VERSION 5.8 ;
BUSBITCHARS "[]" ;
DIVIDERCHAR "/" ;
UNITS
    DATABASE MICRONS 1000 ;
END UNITS

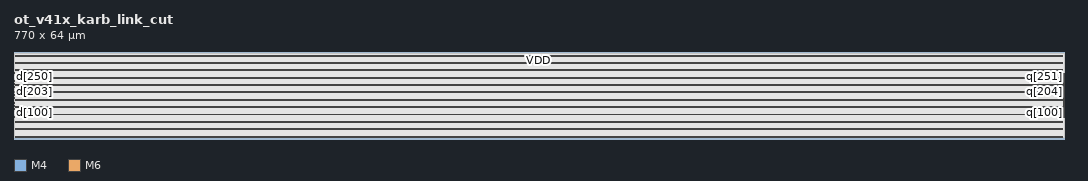
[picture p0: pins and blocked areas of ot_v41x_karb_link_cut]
MACRO ot_v41x_karb_link_cut
  FOREIGN ot_v41x_karb_link_cut 0 0 ;
  CLASS BLOCK ;
  SIZE 770 BY 64 ;
  PIN clk
    DIRECTION INPUT ;
    USE SIGNAL ;
    PORT
      LAYER M4 ;
        RECT  0 15.552 0.084 15.576 ;
    END
  END clk
  PIN d[0]
    DIRECTION INPUT ;
    USE SIGNAL ;
    PORT
      LAYER M4 ;
        RECT  0 15.648 0.084 15.672 ;
    END
  END d[0]
  PIN d[100]
    DIRECTION INPUT ;
    USE SIGNAL ;
    PORT
      LAYER M4 ;
        RECT  0 25.248 0.084 25.272 ;
    END
  END d[100]
  PIN d[101]
    DIRECTION INPUT ;
    USE SIGNAL ;
    PORT
      LAYER M4 ;
        RECT  0 25.344 0.084 25.368 ;
    END
  END d[101]
  PIN d[102]
    DIRECTION INPUT ;
    USE SIGNAL ;
    PORT
      LAYER M4 ;
        RECT  0 25.44 0.084 25.464 ;
    END
  END d[102]
  PIN d[103]
    DIRECTION INPUT ;
    USE SIGNAL ;
    PORT
      LAYER M4 ;
        RECT  0 25.536 0.084 25.56 ;
    END
  END d[103]
  PIN d[104]
    DIRECTION INPUT ;
    USE SIGNAL ;
    PORT
      LAYER M4 ;
        RECT  0 25.632 0.084 25.656 ;
    END
  END d[104]
  PIN d[105]
    DIRECTION INPUT ;
    USE SIGNAL ;
    PORT
      LAYER M4 ;
        RECT  0 25.728 0.084 25.752 ;
    END
  END d[105]
  PIN d[106]
    DIRECTION INPUT ;
    USE SIGNAL ;
    PORT
      LAYER M4 ;
        RECT  0 25.824 0.084 25.848 ;
    END
  END d[106]
  PIN d[107]
    DIRECTION INPUT ;
    USE SIGNAL ;
    PORT
      LAYER M4 ;
        RECT  0 25.92 0.084 25.944 ;
    END
  END d[107]
  PIN d[108]
    DIRECTION INPUT ;
    USE SIGNAL ;
    PORT
      LAYER M4 ;
        RECT  0 26.016 0.084 26.04 ;
    END
  END d[108]
  PIN d[109]
    DIRECTION INPUT ;
    USE SIGNAL ;
    PORT
      LAYER M4 ;
        RECT  0 26.112 0.084 26.136 ;
    END
  END d[109]
  PIN d[10]
    DIRECTION INPUT ;
    USE SIGNAL ;
    PORT
      LAYER M4 ;
        RECT  0 16.608 0.084 16.632 ;
    END
  END d[10]
  PIN d[110]
    DIRECTION INPUT ;
    USE SIGNAL ;
    PORT
      LAYER M4 ;
        RECT  0 26.208 0.084 26.232 ;
    END
  END d[110]
  PIN d[111]
    DIRECTION INPUT ;
    USE SIGNAL ;
    PORT
      LAYER M4 ;
        RECT  0 26.304 0.084 26.328 ;
    END
  END d[111]
  PIN d[112]
    DIRECTION INPUT ;
    USE SIGNAL ;
    PORT
      LAYER M4 ;
        RECT  0 26.4 0.084 26.424 ;
    END
  END d[112]
  PIN d[113]
    DIRECTION INPUT ;
    USE SIGNAL ;
    PORT
      LAYER M4 ;
        RECT  0 26.496 0.084 26.52 ;
    END
  END d[113]
  PIN d[114]
    DIRECTION INPUT ;
    USE SIGNAL ;
    PORT
      LAYER M4 ;
        RECT  0 26.592 0.084 26.616 ;
    END
  END d[114]
  PIN d[115]
    DIRECTION INPUT ;
    USE SIGNAL ;
    PORT
      LAYER M4 ;
        RECT  0 26.688 0.084 26.712 ;
    END
  END d[115]
  PIN d[116]
    DIRECTION INPUT ;
    USE SIGNAL ;
    PORT
      LAYER M4 ;
        RECT  0 26.784 0.084 26.808 ;
    END
  END d[116]
  PIN d[117]
    DIRECTION INPUT ;
    USE SIGNAL ;
    PORT
      LAYER M4 ;
        RECT  0 26.88 0.084 26.904 ;
    END
  END d[117]
  PIN d[118]
    DIRECTION INPUT ;
    USE SIGNAL ;
    PORT
      LAYER M4 ;
        RECT  0 26.976 0.084 27 ;
    END
  END d[118]
  PIN d[119]
    DIRECTION INPUT ;
    USE SIGNAL ;
    PORT
      LAYER M4 ;
        RECT  0 27.072 0.084 27.096 ;
    END
  END d[119]
  PIN d[11]
    DIRECTION INPUT ;
    USE SIGNAL ;
    PORT
      LAYER M4 ;
        RECT  0 16.704 0.084 16.728 ;
    END
  END d[11]
  PIN d[120]
    DIRECTION INPUT ;
    USE SIGNAL ;
    PORT
      LAYER M4 ;
        RECT  0 27.168 0.084 27.192 ;
    END
  END d[120]
  PIN d[121]
    DIRECTION INPUT ;
    USE SIGNAL ;
    PORT
      LAYER M4 ;
        RECT  0 27.264 0.084 27.288 ;
    END
  END d[121]
  PIN d[122]
    DIRECTION INPUT ;
    USE SIGNAL ;
    PORT
      LAYER M4 ;
        RECT  0 27.36 0.084 27.384 ;
    END
  END d[122]
  PIN d[123]
    DIRECTION INPUT ;
    USE SIGNAL ;
    PORT
      LAYER M4 ;
        RECT  0 27.456 0.084 27.48 ;
    END
  END d[123]
  PIN d[124]
    DIRECTION INPUT ;
    USE SIGNAL ;
    PORT
      LAYER M4 ;
        RECT  0 27.552 0.084 27.576 ;
    END
  END d[124]
  PIN d[125]
    DIRECTION INPUT ;
    USE SIGNAL ;
    PORT
      LAYER M4 ;
        RECT  0 27.648 0.084 27.672 ;
    END
  END d[125]
  PIN d[126]
    DIRECTION INPUT ;
    USE SIGNAL ;
    PORT
      LAYER M4 ;
        RECT  0 27.744 0.084 27.768 ;
    END
  END d[126]
  PIN d[127]
    DIRECTION INPUT ;
    USE SIGNAL ;
    PORT
      LAYER M4 ;
        RECT  0 27.84 0.084 27.864 ;
    END
  END d[127]
  PIN d[128]
    DIRECTION INPUT ;
    USE SIGNAL ;
    PORT
      LAYER M4 ;
        RECT  0 27.936 0.084 27.96 ;
    END
  END d[128]
  PIN d[129]
    DIRECTION INPUT ;
    USE SIGNAL ;
    PORT
      LAYER M4 ;
        RECT  0 28.032 0.084 28.056 ;
    END
  END d[129]
  PIN d[12]
    DIRECTION INPUT ;
    USE SIGNAL ;
    PORT
      LAYER M4 ;
        RECT  0 16.8 0.084 16.824 ;
    END
  END d[12]
  PIN d[130]
    DIRECTION INPUT ;
    USE SIGNAL ;
    PORT
      LAYER M4 ;
        RECT  0 28.128 0.084 28.152 ;
    END
  END d[130]
  PIN d[131]
    DIRECTION INPUT ;
    USE SIGNAL ;
    PORT
      LAYER M4 ;
        RECT  0 28.224 0.084 28.248 ;
    END
  END d[131]
  PIN d[132]
    DIRECTION INPUT ;
    USE SIGNAL ;
    PORT
      LAYER M4 ;
        RECT  0 28.32 0.084 28.344 ;
    END
  END d[132]
  PIN d[133]
    DIRECTION INPUT ;
    USE SIGNAL ;
    PORT
      LAYER M4 ;
        RECT  0 28.416 0.084 28.44 ;
    END
  END d[133]
  PIN d[134]
    DIRECTION INPUT ;
    USE SIGNAL ;
    PORT
      LAYER M4 ;
        RECT  0 28.512 0.084 28.536 ;
    END
  END d[134]
  PIN d[135]
    DIRECTION INPUT ;
    USE SIGNAL ;
    PORT
      LAYER M4 ;
        RECT  0 28.608 0.084 28.632 ;
    END
  END d[135]
  PIN d[136]
    DIRECTION INPUT ;
    USE SIGNAL ;
    PORT
      LAYER M4 ;
        RECT  0 28.704 0.084 28.728 ;
    END
  END d[136]
  PIN d[137]
    DIRECTION INPUT ;
    USE SIGNAL ;
    PORT
      LAYER M4 ;
        RECT  0 28.8 0.084 28.824 ;
    END
  END d[137]
  PIN d[138]
    DIRECTION INPUT ;
    USE SIGNAL ;
    PORT
      LAYER M4 ;
        RECT  0 28.896 0.084 28.92 ;
    END
  END d[138]
  PIN d[139]
    DIRECTION INPUT ;
    USE SIGNAL ;
    PORT
      LAYER M4 ;
        RECT  0 28.992 0.084 29.016 ;
    END
  END d[139]
  PIN d[13]
    DIRECTION INPUT ;
    USE SIGNAL ;
    PORT
      LAYER M4 ;
        RECT  0 16.896 0.084 16.92 ;
    END
  END d[13]
  PIN d[140]
    DIRECTION INPUT ;
    USE SIGNAL ;
    PORT
      LAYER M4 ;
        RECT  0 29.088 0.084 29.112 ;
    END
  END d[140]
  PIN d[141]
    DIRECTION INPUT ;
    USE SIGNAL ;
    PORT
      LAYER M4 ;
        RECT  0 29.184 0.084 29.208 ;
    END
  END d[141]
  PIN d[142]
    DIRECTION INPUT ;
    USE SIGNAL ;
    PORT
      LAYER M4 ;
        RECT  0 29.28 0.084 29.304 ;
    END
  END d[142]
  PIN d[143]
    DIRECTION INPUT ;
    USE SIGNAL ;
    PORT
      LAYER M4 ;
        RECT  0 29.376 0.084 29.4 ;
    END
  END d[143]
  PIN d[144]
    DIRECTION INPUT ;
    USE SIGNAL ;
    PORT
      LAYER M4 ;
        RECT  0 29.472 0.084 29.496 ;
    END
  END d[144]
  PIN d[145]
    DIRECTION INPUT ;
    USE SIGNAL ;
    PORT
      LAYER M4 ;
        RECT  0 29.568 0.084 29.592 ;
    END
  END d[145]
  PIN d[146]
    DIRECTION INPUT ;
    USE SIGNAL ;
    PORT
      LAYER M4 ;
        RECT  0 29.664 0.084 29.688 ;
    END
  END d[146]
  PIN d[147]
    DIRECTION INPUT ;
    USE SIGNAL ;
    PORT
      LAYER M4 ;
        RECT  0 29.76 0.084 29.784 ;
    END
  END d[147]
  PIN d[148]
    DIRECTION INPUT ;
    USE SIGNAL ;
    PORT
      LAYER M4 ;
        RECT  0 29.856 0.084 29.88 ;
    END
  END d[148]
  PIN d[149]
    DIRECTION INPUT ;
    USE SIGNAL ;
    PORT
      LAYER M4 ;
        RECT  0 29.952 0.084 29.976 ;
    END
  END d[149]
  PIN d[14]
    DIRECTION INPUT ;
    USE SIGNAL ;
    PORT
      LAYER M4 ;
        RECT  0 16.992 0.084 17.016 ;
    END
  END d[14]
  PIN d[150]
    DIRECTION INPUT ;
    USE SIGNAL ;
    PORT
      LAYER M4 ;
        RECT  0 30.048 0.084 30.072 ;
    END
  END d[150]
  PIN d[151]
    DIRECTION INPUT ;
    USE SIGNAL ;
    PORT
      LAYER M4 ;
        RECT  0 30.144 0.084 30.168 ;
    END
  END d[151]
  PIN d[152]
    DIRECTION INPUT ;
    USE SIGNAL ;
    PORT
      LAYER M4 ;
        RECT  0 30.24 0.084 30.264 ;
    END
  END d[152]
  PIN d[153]
    DIRECTION INPUT ;
    USE SIGNAL ;
    PORT
      LAYER M4 ;
        RECT  0 30.336 0.084 30.36 ;
    END
  END d[153]
  PIN d[154]
    DIRECTION INPUT ;
    USE SIGNAL ;
    PORT
      LAYER M4 ;
        RECT  0 30.432 0.084 30.456 ;
    END
  END d[154]
  PIN d[155]
    DIRECTION INPUT ;
    USE SIGNAL ;
    PORT
      LAYER M4 ;
        RECT  0 30.528 0.084 30.552 ;
    END
  END d[155]
  PIN d[156]
    DIRECTION INPUT ;
    USE SIGNAL ;
    PORT
      LAYER M4 ;
        RECT  0 30.624 0.084 30.648 ;
    END
  END d[156]
  PIN d[157]
    DIRECTION INPUT ;
    USE SIGNAL ;
    PORT
      LAYER M4 ;
        RECT  0 30.72 0.084 30.744 ;
    END
  END d[157]
  PIN d[158]
    DIRECTION INPUT ;
    USE SIGNAL ;
    PORT
      LAYER M4 ;
        RECT  0 30.816 0.084 30.84 ;
    END
  END d[158]
  PIN d[159]
    DIRECTION INPUT ;
    USE SIGNAL ;
    PORT
      LAYER M4 ;
        RECT  0 30.912 0.084 30.936 ;
    END
  END d[159]
  PIN d[15]
    DIRECTION INPUT ;
    USE SIGNAL ;
    PORT
      LAYER M4 ;
        RECT  0 17.088 0.084 17.112 ;
    END
  END d[15]
  PIN d[160]
    DIRECTION INPUT ;
    USE SIGNAL ;
    PORT
      LAYER M4 ;
        RECT  0 31.008 0.084 31.032 ;
    END
  END d[160]
  PIN d[161]
    DIRECTION INPUT ;
    USE SIGNAL ;
    PORT
      LAYER M4 ;
        RECT  0 31.104 0.084 31.128 ;
    END
  END d[161]
  PIN d[162]
    DIRECTION INPUT ;
    USE SIGNAL ;
    PORT
      LAYER M4 ;
        RECT  0 31.2 0.084 31.224 ;
    END
  END d[162]
  PIN d[163]
    DIRECTION INPUT ;
    USE SIGNAL ;
    PORT
      LAYER M4 ;
        RECT  0 31.296 0.084 31.32 ;
    END
  END d[163]
  PIN d[164]
    DIRECTION INPUT ;
    USE SIGNAL ;
    PORT
      LAYER M4 ;
        RECT  0 31.392 0.084 31.416 ;
    END
  END d[164]
  PIN d[165]
    DIRECTION INPUT ;
    USE SIGNAL ;
    PORT
      LAYER M4 ;
        RECT  0 31.488 0.084 31.512 ;
    END
  END d[165]
  PIN d[166]
    DIRECTION INPUT ;
    USE SIGNAL ;
    PORT
      LAYER M4 ;
        RECT  0 31.584 0.084 31.608 ;
    END
  END d[166]
  PIN d[167]
    DIRECTION INPUT ;
    USE SIGNAL ;
    PORT
      LAYER M4 ;
        RECT  0 31.68 0.084 31.704 ;
    END
  END d[167]
  PIN d[168]
    DIRECTION INPUT ;
    USE SIGNAL ;
    PORT
      LAYER M4 ;
        RECT  0 31.776 0.084 31.8 ;
    END
  END d[168]
  PIN d[169]
    DIRECTION INPUT ;
    USE SIGNAL ;
    PORT
      LAYER M4 ;
        RECT  0 31.872 0.084 31.896 ;
    END
  END d[169]
  PIN d[16]
    DIRECTION INPUT ;
    USE SIGNAL ;
    PORT
      LAYER M4 ;
        RECT  0 17.184 0.084 17.208 ;
    END
  END d[16]
  PIN d[170]
    DIRECTION INPUT ;
    USE SIGNAL ;
    PORT
      LAYER M4 ;
        RECT  0 31.968 0.084 31.992 ;
    END
  END d[170]
  PIN d[171]
    DIRECTION INPUT ;
    USE SIGNAL ;
    PORT
      LAYER M4 ;
        RECT  0 32.064 0.084 32.088 ;
    END
  END d[171]
  PIN d[172]
    DIRECTION INPUT ;
    USE SIGNAL ;
    PORT
      LAYER M4 ;
        RECT  0 32.16 0.084 32.184 ;
    END
  END d[172]
  PIN d[173]
    DIRECTION INPUT ;
    USE SIGNAL ;
    PORT
      LAYER M4 ;
        RECT  0 32.256 0.084 32.28 ;
    END
  END d[173]
  PIN d[174]
    DIRECTION INPUT ;
    USE SIGNAL ;
    PORT
      LAYER M4 ;
        RECT  0 32.352 0.084 32.376 ;
    END
  END d[174]
  PIN d[175]
    DIRECTION INPUT ;
    USE SIGNAL ;
    PORT
      LAYER M4 ;
        RECT  0 32.448 0.084 32.472 ;
    END
  END d[175]
  PIN d[176]
    DIRECTION INPUT ;
    USE SIGNAL ;
    PORT
      LAYER M4 ;
        RECT  0 32.544 0.084 32.568 ;
    END
  END d[176]
  PIN d[177]
    DIRECTION INPUT ;
    USE SIGNAL ;
    PORT
      LAYER M4 ;
        RECT  0 32.64 0.084 32.664 ;
    END
  END d[177]
  PIN d[178]
    DIRECTION INPUT ;
    USE SIGNAL ;
    PORT
      LAYER M4 ;
        RECT  0 32.736 0.084 32.76 ;
    END
  END d[178]
  PIN d[179]
    DIRECTION INPUT ;
    USE SIGNAL ;
    PORT
      LAYER M4 ;
        RECT  0 32.832 0.084 32.856 ;
    END
  END d[179]
  PIN d[17]
    DIRECTION INPUT ;
    USE SIGNAL ;
    PORT
      LAYER M4 ;
        RECT  0 17.28 0.084 17.304 ;
    END
  END d[17]
  PIN d[180]
    DIRECTION INPUT ;
    USE SIGNAL ;
    PORT
      LAYER M4 ;
        RECT  0 32.928 0.084 32.952 ;
    END
  END d[180]
  PIN d[181]
    DIRECTION INPUT ;
    USE SIGNAL ;
    PORT
      LAYER M4 ;
        RECT  0 33.024 0.084 33.048 ;
    END
  END d[181]
  PIN d[182]
    DIRECTION INPUT ;
    USE SIGNAL ;
    PORT
      LAYER M4 ;
        RECT  0 33.12 0.084 33.144 ;
    END
  END d[182]
  PIN d[183]
    DIRECTION INPUT ;
    USE SIGNAL ;
    PORT
      LAYER M4 ;
        RECT  0 33.216 0.084 33.24 ;
    END
  END d[183]
  PIN d[184]
    DIRECTION INPUT ;
    USE SIGNAL ;
    PORT
      LAYER M4 ;
        RECT  0 33.312 0.084 33.336 ;
    END
  END d[184]
  PIN d[185]
    DIRECTION INPUT ;
    USE SIGNAL ;
    PORT
      LAYER M4 ;
        RECT  0 33.408 0.084 33.432 ;
    END
  END d[185]
  PIN d[186]
    DIRECTION INPUT ;
    USE SIGNAL ;
    PORT
      LAYER M4 ;
        RECT  0 33.504 0.084 33.528 ;
    END
  END d[186]
  PIN d[187]
    DIRECTION INPUT ;
    USE SIGNAL ;
    PORT
      LAYER M4 ;
        RECT  0 33.6 0.084 33.624 ;
    END
  END d[187]
  PIN d[188]
    DIRECTION INPUT ;
    USE SIGNAL ;
    PORT
      LAYER M4 ;
        RECT  0 33.696 0.084 33.72 ;
    END
  END d[188]
  PIN d[189]
    DIRECTION INPUT ;
    USE SIGNAL ;
    PORT
      LAYER M4 ;
        RECT  0 33.792 0.084 33.816 ;
    END
  END d[189]
  PIN d[18]
    DIRECTION INPUT ;
    USE SIGNAL ;
    PORT
      LAYER M4 ;
        RECT  0 17.376 0.084 17.4 ;
    END
  END d[18]
  PIN d[190]
    DIRECTION INPUT ;
    USE SIGNAL ;
    PORT
      LAYER M4 ;
        RECT  0 33.888 0.084 33.912 ;
    END
  END d[190]
  PIN d[191]
    DIRECTION INPUT ;
    USE SIGNAL ;
    PORT
      LAYER M4 ;
        RECT  0 33.984 0.084 34.008 ;
    END
  END d[191]
  PIN d[192]
    DIRECTION INPUT ;
    USE SIGNAL ;
    PORT
      LAYER M4 ;
        RECT  0 34.08 0.084 34.104 ;
    END
  END d[192]
  PIN d[193]
    DIRECTION INPUT ;
    USE SIGNAL ;
    PORT
      LAYER M4 ;
        RECT  0 34.176 0.084 34.2 ;
    END
  END d[193]
  PIN d[194]
    DIRECTION INPUT ;
    USE SIGNAL ;
    PORT
      LAYER M4 ;
        RECT  0 34.272 0.084 34.296 ;
    END
  END d[194]
  PIN d[195]
    DIRECTION INPUT ;
    USE SIGNAL ;
    PORT
      LAYER M4 ;
        RECT  0 34.368 0.084 34.392 ;
    END
  END d[195]
  PIN d[196]
    DIRECTION INPUT ;
    USE SIGNAL ;
    PORT
      LAYER M4 ;
        RECT  0 34.464 0.084 34.488 ;
    END
  END d[196]
  PIN d[197]
    DIRECTION INPUT ;
    USE SIGNAL ;
    PORT
      LAYER M4 ;
        RECT  0 34.56 0.084 34.584 ;
    END
  END d[197]
  PIN d[198]
    DIRECTION INPUT ;
    USE SIGNAL ;
    PORT
      LAYER M4 ;
        RECT  0 34.656 0.084 34.68 ;
    END
  END d[198]
  PIN d[199]
    DIRECTION INPUT ;
    USE SIGNAL ;
    PORT
      LAYER M4 ;
        RECT  0 34.752 0.084 34.776 ;
    END
  END d[199]
  PIN d[19]
    DIRECTION INPUT ;
    USE SIGNAL ;
    PORT
      LAYER M4 ;
        RECT  0 17.472 0.084 17.496 ;
    END
  END d[19]
  PIN d[1]
    DIRECTION INPUT ;
    USE SIGNAL ;
    PORT
      LAYER M4 ;
        RECT  0 15.744 0.084 15.768 ;
    END
  END d[1]
  PIN d[200]
    DIRECTION INPUT ;
    USE SIGNAL ;
    PORT
      LAYER M4 ;
        RECT  0 34.848 0.084 34.872 ;
    END
  END d[200]
  PIN d[201]
    DIRECTION INPUT ;
    USE SIGNAL ;
    PORT
      LAYER M4 ;
        RECT  0 34.944 0.084 34.968 ;
    END
  END d[201]
  PIN d[202]
    DIRECTION INPUT ;
    USE SIGNAL ;
    PORT
      LAYER M4 ;
        RECT  0 35.04 0.084 35.064 ;
    END
  END d[202]
  PIN d[203]
    DIRECTION INPUT ;
    USE SIGNAL ;
    PORT
      LAYER M4 ;
        RECT  0 35.136 0.084 35.16 ;
    END
  END d[203]
  PIN d[204]
    DIRECTION INPUT ;
    USE SIGNAL ;
    PORT
      LAYER M4 ;
        RECT  0 35.232 0.084 35.256 ;
    END
  END d[204]
  PIN d[205]
    DIRECTION INPUT ;
    USE SIGNAL ;
    PORT
      LAYER M4 ;
        RECT  0 35.328 0.084 35.352 ;
    END
  END d[205]
  PIN d[206]
    DIRECTION INPUT ;
    USE SIGNAL ;
    PORT
      LAYER M4 ;
        RECT  0 35.424 0.084 35.448 ;
    END
  END d[206]
  PIN d[207]
    DIRECTION INPUT ;
    USE SIGNAL ;
    PORT
      LAYER M4 ;
        RECT  0 35.52 0.084 35.544 ;
    END
  END d[207]
  PIN d[208]
    DIRECTION INPUT ;
    USE SIGNAL ;
    PORT
      LAYER M4 ;
        RECT  0 35.616 0.084 35.64 ;
    END
  END d[208]
  PIN d[209]
    DIRECTION INPUT ;
    USE SIGNAL ;
    PORT
      LAYER M4 ;
        RECT  0 35.712 0.084 35.736 ;
    END
  END d[209]
  PIN d[20]
    DIRECTION INPUT ;
    USE SIGNAL ;
    PORT
      LAYER M4 ;
        RECT  0 17.568 0.084 17.592 ;
    END
  END d[20]
  PIN d[210]
    DIRECTION INPUT ;
    USE SIGNAL ;
    PORT
      LAYER M4 ;
        RECT  0 35.808 0.084 35.832 ;
    END
  END d[210]
  PIN d[211]
    DIRECTION INPUT ;
    USE SIGNAL ;
    PORT
      LAYER M4 ;
        RECT  0 35.904 0.084 35.928 ;
    END
  END d[211]
  PIN d[212]
    DIRECTION INPUT ;
    USE SIGNAL ;
    PORT
      LAYER M4 ;
        RECT  0 36 0.084 36.024 ;
    END
  END d[212]
  PIN d[213]
    DIRECTION INPUT ;
    USE SIGNAL ;
    PORT
      LAYER M4 ;
        RECT  0 36.096 0.084 36.12 ;
    END
  END d[213]
  PIN d[214]
    DIRECTION INPUT ;
    USE SIGNAL ;
    PORT
      LAYER M4 ;
        RECT  0 36.192 0.084 36.216 ;
    END
  END d[214]
  PIN d[215]
    DIRECTION INPUT ;
    USE SIGNAL ;
    PORT
      LAYER M4 ;
        RECT  0 36.288 0.084 36.312 ;
    END
  END d[215]
  PIN d[216]
    DIRECTION INPUT ;
    USE SIGNAL ;
    PORT
      LAYER M4 ;
        RECT  0 36.384 0.084 36.408 ;
    END
  END d[216]
  PIN d[217]
    DIRECTION INPUT ;
    USE SIGNAL ;
    PORT
      LAYER M4 ;
        RECT  0 36.48 0.084 36.504 ;
    END
  END d[217]
  PIN d[218]
    DIRECTION INPUT ;
    USE SIGNAL ;
    PORT
      LAYER M4 ;
        RECT  0 36.576 0.084 36.6 ;
    END
  END d[218]
  PIN d[219]
    DIRECTION INPUT ;
    USE SIGNAL ;
    PORT
      LAYER M4 ;
        RECT  0 36.672 0.084 36.696 ;
    END
  END d[219]
  PIN d[21]
    DIRECTION INPUT ;
    USE SIGNAL ;
    PORT
      LAYER M4 ;
        RECT  0 17.664 0.084 17.688 ;
    END
  END d[21]
  PIN d[220]
    DIRECTION INPUT ;
    USE SIGNAL ;
    PORT
      LAYER M4 ;
        RECT  0 36.768 0.084 36.792 ;
    END
  END d[220]
  PIN d[221]
    DIRECTION INPUT ;
    USE SIGNAL ;
    PORT
      LAYER M4 ;
        RECT  0 36.864 0.084 36.888 ;
    END
  END d[221]
  PIN d[222]
    DIRECTION INPUT ;
    USE SIGNAL ;
    PORT
      LAYER M4 ;
        RECT  0 36.96 0.084 36.984 ;
    END
  END d[222]
  PIN d[223]
    DIRECTION INPUT ;
    USE SIGNAL ;
    PORT
      LAYER M4 ;
        RECT  0 37.056 0.084 37.08 ;
    END
  END d[223]
  PIN d[224]
    DIRECTION INPUT ;
    USE SIGNAL ;
    PORT
      LAYER M4 ;
        RECT  0 37.152 0.084 37.176 ;
    END
  END d[224]
  PIN d[225]
    DIRECTION INPUT ;
    USE SIGNAL ;
    PORT
      LAYER M4 ;
        RECT  0 37.248 0.084 37.272 ;
    END
  END d[225]
  PIN d[226]
    DIRECTION INPUT ;
    USE SIGNAL ;
    PORT
      LAYER M4 ;
        RECT  0 37.344 0.084 37.368 ;
    END
  END d[226]
  PIN d[227]
    DIRECTION INPUT ;
    USE SIGNAL ;
    PORT
      LAYER M4 ;
        RECT  0 37.44 0.084 37.464 ;
    END
  END d[227]
  PIN d[228]
    DIRECTION INPUT ;
    USE SIGNAL ;
    PORT
      LAYER M4 ;
        RECT  0 37.536 0.084 37.56 ;
    END
  END d[228]
  PIN d[229]
    DIRECTION INPUT ;
    USE SIGNAL ;
    PORT
      LAYER M4 ;
        RECT  0 37.632 0.084 37.656 ;
    END
  END d[229]
  PIN d[22]
    DIRECTION INPUT ;
    USE SIGNAL ;
    PORT
      LAYER M4 ;
        RECT  0 17.76 0.084 17.784 ;
    END
  END d[22]
  PIN d[230]
    DIRECTION INPUT ;
    USE SIGNAL ;
    PORT
      LAYER M4 ;
        RECT  0 37.728 0.084 37.752 ;
    END
  END d[230]
  PIN d[231]
    DIRECTION INPUT ;
    USE SIGNAL ;
    PORT
      LAYER M4 ;
        RECT  0 37.824 0.084 37.848 ;
    END
  END d[231]
  PIN d[232]
    DIRECTION INPUT ;
    USE SIGNAL ;
    PORT
      LAYER M4 ;
        RECT  0 37.92 0.084 37.944 ;
    END
  END d[232]
  PIN d[233]
    DIRECTION INPUT ;
    USE SIGNAL ;
    PORT
      LAYER M4 ;
        RECT  0 38.016 0.084 38.04 ;
    END
  END d[233]
  PIN d[234]
    DIRECTION INPUT ;
    USE SIGNAL ;
    PORT
      LAYER M4 ;
        RECT  0 38.112 0.084 38.136 ;
    END
  END d[234]
  PIN d[235]
    DIRECTION INPUT ;
    USE SIGNAL ;
    PORT
      LAYER M4 ;
        RECT  0 38.208 0.084 38.232 ;
    END
  END d[235]
  PIN d[236]
    DIRECTION INPUT ;
    USE SIGNAL ;
    PORT
      LAYER M4 ;
        RECT  0 38.304 0.084 38.328 ;
    END
  END d[236]
  PIN d[237]
    DIRECTION INPUT ;
    USE SIGNAL ;
    PORT
      LAYER M4 ;
        RECT  0 38.4 0.084 38.424 ;
    END
  END d[237]
  PIN d[238]
    DIRECTION INPUT ;
    USE SIGNAL ;
    PORT
      LAYER M4 ;
        RECT  0 38.496 0.084 38.52 ;
    END
  END d[238]
  PIN d[239]
    DIRECTION INPUT ;
    USE SIGNAL ;
    PORT
      LAYER M4 ;
        RECT  0 38.592 0.084 38.616 ;
    END
  END d[239]
  PIN d[23]
    DIRECTION INPUT ;
    USE SIGNAL ;
    PORT
      LAYER M4 ;
        RECT  0 17.856 0.084 17.88 ;
    END
  END d[23]
  PIN d[240]
    DIRECTION INPUT ;
    USE SIGNAL ;
    PORT
      LAYER M4 ;
        RECT  0 38.688 0.084 38.712 ;
    END
  END d[240]
  PIN d[241]
    DIRECTION INPUT ;
    USE SIGNAL ;
    PORT
      LAYER M4 ;
        RECT  0 38.784 0.084 38.808 ;
    END
  END d[241]
  PIN d[242]
    DIRECTION INPUT ;
    USE SIGNAL ;
    PORT
      LAYER M4 ;
        RECT  0 38.88 0.084 38.904 ;
    END
  END d[242]
  PIN d[243]
    DIRECTION INPUT ;
    USE SIGNAL ;
    PORT
      LAYER M4 ;
        RECT  0 38.976 0.084 39 ;
    END
  END d[243]
  PIN d[244]
    DIRECTION INPUT ;
    USE SIGNAL ;
    PORT
      LAYER M4 ;
        RECT  0 39.072 0.084 39.096 ;
    END
  END d[244]
  PIN d[245]
    DIRECTION INPUT ;
    USE SIGNAL ;
    PORT
      LAYER M4 ;
        RECT  0 39.168 0.084 39.192 ;
    END
  END d[245]
  PIN d[246]
    DIRECTION INPUT ;
    USE SIGNAL ;
    PORT
      LAYER M4 ;
        RECT  0 39.264 0.084 39.288 ;
    END
  END d[246]
  PIN d[247]
    DIRECTION INPUT ;
    USE SIGNAL ;
    PORT
      LAYER M4 ;
        RECT  0 39.36 0.084 39.384 ;
    END
  END d[247]
  PIN d[248]
    DIRECTION INPUT ;
    USE SIGNAL ;
    PORT
      LAYER M4 ;
        RECT  0 39.456 0.084 39.48 ;
    END
  END d[248]
  PIN d[249]
    DIRECTION INPUT ;
    USE SIGNAL ;
    PORT
      LAYER M4 ;
        RECT  0 39.552 0.084 39.576 ;
    END
  END d[249]
  PIN d[24]
    DIRECTION INPUT ;
    USE SIGNAL ;
    PORT
      LAYER M4 ;
        RECT  0 17.952 0.084 17.976 ;
    END
  END d[24]
  PIN d[250]
    DIRECTION INPUT ;
    USE SIGNAL ;
    PORT
      LAYER M4 ;
        RECT  0 39.648 0.084 39.672 ;
    END
  END d[250]
  PIN d[251]
    DIRECTION INPUT ;
    USE SIGNAL ;
    PORT
      LAYER M4 ;
        RECT  0 39.744 0.084 39.768 ;
    END
  END d[251]
  PIN d[252]
    DIRECTION INPUT ;
    USE SIGNAL ;
    PORT
      LAYER M4 ;
        RECT  0 39.84 0.084 39.864 ;
    END
  END d[252]
  PIN d[253]
    DIRECTION INPUT ;
    USE SIGNAL ;
    PORT
      LAYER M4 ;
        RECT  0 39.936 0.084 39.96 ;
    END
  END d[253]
  PIN d[254]
    DIRECTION INPUT ;
    USE SIGNAL ;
    PORT
      LAYER M4 ;
        RECT  0 40.032 0.084 40.056 ;
    END
  END d[254]
  PIN d[255]
    DIRECTION INPUT ;
    USE SIGNAL ;
    PORT
      LAYER M4 ;
        RECT  0 40.128 0.084 40.152 ;
    END
  END d[255]
  PIN d[256]
    DIRECTION INPUT ;
    USE SIGNAL ;
    PORT
      LAYER M4 ;
        RECT  0 40.224 0.084 40.248 ;
    END
  END d[256]
  PIN d[257]
    DIRECTION INPUT ;
    USE SIGNAL ;
    PORT
      LAYER M4 ;
        RECT  0 40.32 0.084 40.344 ;
    END
  END d[257]
  PIN d[258]
    DIRECTION INPUT ;
    USE SIGNAL ;
    PORT
      LAYER M4 ;
        RECT  0 40.416 0.084 40.44 ;
    END
  END d[258]
  PIN d[259]
    DIRECTION INPUT ;
    USE SIGNAL ;
    PORT
      LAYER M4 ;
        RECT  0 40.512 0.084 40.536 ;
    END
  END d[259]
  PIN d[25]
    DIRECTION INPUT ;
    USE SIGNAL ;
    PORT
      LAYER M4 ;
        RECT  0 18.048 0.084 18.072 ;
    END
  END d[25]
  PIN d[260]
    DIRECTION INPUT ;
    USE SIGNAL ;
    PORT
      LAYER M4 ;
        RECT  0 40.608 0.084 40.632 ;
    END
  END d[260]
  PIN d[261]
    DIRECTION INPUT ;
    USE SIGNAL ;
    PORT
      LAYER M4 ;
        RECT  0 40.704 0.084 40.728 ;
    END
  END d[261]
  PIN d[262]
    DIRECTION INPUT ;
    USE SIGNAL ;
    PORT
      LAYER M4 ;
        RECT  0 40.8 0.084 40.824 ;
    END
  END d[262]
  PIN d[263]
    DIRECTION INPUT ;
    USE SIGNAL ;
    PORT
      LAYER M4 ;
        RECT  0 40.896 0.084 40.92 ;
    END
  END d[263]
  PIN d[264]
    DIRECTION INPUT ;
    USE SIGNAL ;
    PORT
      LAYER M4 ;
        RECT  0 40.992 0.084 41.016 ;
    END
  END d[264]
  PIN d[265]
    DIRECTION INPUT ;
    USE SIGNAL ;
    PORT
      LAYER M4 ;
        RECT  0 41.088 0.084 41.112 ;
    END
  END d[265]
  PIN d[266]
    DIRECTION INPUT ;
    USE SIGNAL ;
    PORT
      LAYER M4 ;
        RECT  0 41.184 0.084 41.208 ;
    END
  END d[266]
  PIN d[267]
    DIRECTION INPUT ;
    USE SIGNAL ;
    PORT
      LAYER M4 ;
        RECT  0 41.28 0.084 41.304 ;
    END
  END d[267]
  PIN d[268]
    DIRECTION INPUT ;
    USE SIGNAL ;
    PORT
      LAYER M4 ;
        RECT  0 41.376 0.084 41.4 ;
    END
  END d[268]
  PIN d[269]
    DIRECTION INPUT ;
    USE SIGNAL ;
    PORT
      LAYER M4 ;
        RECT  0 41.472 0.084 41.496 ;
    END
  END d[269]
  PIN d[26]
    DIRECTION INPUT ;
    USE SIGNAL ;
    PORT
      LAYER M4 ;
        RECT  0 18.144 0.084 18.168 ;
    END
  END d[26]
  PIN d[270]
    DIRECTION INPUT ;
    USE SIGNAL ;
    PORT
      LAYER M4 ;
        RECT  0 41.568 0.084 41.592 ;
    END
  END d[270]
  PIN d[271]
    DIRECTION INPUT ;
    USE SIGNAL ;
    PORT
      LAYER M4 ;
        RECT  0 41.664 0.084 41.688 ;
    END
  END d[271]
  PIN d[272]
    DIRECTION INPUT ;
    USE SIGNAL ;
    PORT
      LAYER M4 ;
        RECT  0 41.76 0.084 41.784 ;
    END
  END d[272]
  PIN d[273]
    DIRECTION INPUT ;
    USE SIGNAL ;
    PORT
      LAYER M4 ;
        RECT  0 41.856 0.084 41.88 ;
    END
  END d[273]
  PIN d[274]
    DIRECTION INPUT ;
    USE SIGNAL ;
    PORT
      LAYER M4 ;
        RECT  0 41.952 0.084 41.976 ;
    END
  END d[274]
  PIN d[275]
    DIRECTION INPUT ;
    USE SIGNAL ;
    PORT
      LAYER M4 ;
        RECT  0 42.048 0.084 42.072 ;
    END
  END d[275]
  PIN d[276]
    DIRECTION INPUT ;
    USE SIGNAL ;
    PORT
      LAYER M4 ;
        RECT  0 42.144 0.084 42.168 ;
    END
  END d[276]
  PIN d[277]
    DIRECTION INPUT ;
    USE SIGNAL ;
    PORT
      LAYER M4 ;
        RECT  0 42.24 0.084 42.264 ;
    END
  END d[277]
  PIN d[278]
    DIRECTION INPUT ;
    USE SIGNAL ;
    PORT
      LAYER M4 ;
        RECT  0 42.336 0.084 42.36 ;
    END
  END d[278]
  PIN d[279]
    DIRECTION INPUT ;
    USE SIGNAL ;
    PORT
      LAYER M4 ;
        RECT  0 42.432 0.084 42.456 ;
    END
  END d[279]
  PIN d[27]
    DIRECTION INPUT ;
    USE SIGNAL ;
    PORT
      LAYER M4 ;
        RECT  0 18.24 0.084 18.264 ;
    END
  END d[27]
  PIN d[280]
    DIRECTION INPUT ;
    USE SIGNAL ;
    PORT
      LAYER M4 ;
        RECT  0 42.528 0.084 42.552 ;
    END
  END d[280]
  PIN d[281]
    DIRECTION INPUT ;
    USE SIGNAL ;
    PORT
      LAYER M4 ;
        RECT  0 42.624 0.084 42.648 ;
    END
  END d[281]
  PIN d[282]
    DIRECTION INPUT ;
    USE SIGNAL ;
    PORT
      LAYER M4 ;
        RECT  0 42.72 0.084 42.744 ;
    END
  END d[282]
  PIN d[283]
    DIRECTION INPUT ;
    USE SIGNAL ;
    PORT
      LAYER M4 ;
        RECT  0 42.816 0.084 42.84 ;
    END
  END d[283]
  PIN d[284]
    DIRECTION INPUT ;
    USE SIGNAL ;
    PORT
      LAYER M4 ;
        RECT  0 42.912 0.084 42.936 ;
    END
  END d[284]
  PIN d[285]
    DIRECTION INPUT ;
    USE SIGNAL ;
    PORT
      LAYER M4 ;
        RECT  0 43.008 0.084 43.032 ;
    END
  END d[285]
  PIN d[286]
    DIRECTION INPUT ;
    USE SIGNAL ;
    PORT
      LAYER M4 ;
        RECT  0 43.104 0.084 43.128 ;
    END
  END d[286]
  PIN d[287]
    DIRECTION INPUT ;
    USE SIGNAL ;
    PORT
      LAYER M4 ;
        RECT  0 43.2 0.084 43.224 ;
    END
  END d[287]
  PIN d[288]
    DIRECTION INPUT ;
    USE SIGNAL ;
    PORT
      LAYER M4 ;
        RECT  0 43.296 0.084 43.32 ;
    END
  END d[288]
  PIN d[289]
    DIRECTION INPUT ;
    USE SIGNAL ;
    PORT
      LAYER M4 ;
        RECT  0 43.392 0.084 43.416 ;
    END
  END d[289]
  PIN d[28]
    DIRECTION INPUT ;
    USE SIGNAL ;
    PORT
      LAYER M4 ;
        RECT  0 18.336 0.084 18.36 ;
    END
  END d[28]
  PIN d[290]
    DIRECTION INPUT ;
    USE SIGNAL ;
    PORT
      LAYER M4 ;
        RECT  0 43.488 0.084 43.512 ;
    END
  END d[290]
  PIN d[291]
    DIRECTION INPUT ;
    USE SIGNAL ;
    PORT
      LAYER M4 ;
        RECT  0 43.584 0.084 43.608 ;
    END
  END d[291]
  PIN d[292]
    DIRECTION INPUT ;
    USE SIGNAL ;
    PORT
      LAYER M4 ;
        RECT  0 43.68 0.084 43.704 ;
    END
  END d[292]
  PIN d[293]
    DIRECTION INPUT ;
    USE SIGNAL ;
    PORT
      LAYER M4 ;
        RECT  0 43.776 0.084 43.8 ;
    END
  END d[293]
  PIN d[294]
    DIRECTION INPUT ;
    USE SIGNAL ;
    PORT
      LAYER M4 ;
        RECT  0 43.872 0.084 43.896 ;
    END
  END d[294]
  PIN d[295]
    DIRECTION INPUT ;
    USE SIGNAL ;
    PORT
      LAYER M4 ;
        RECT  0 43.968 0.084 43.992 ;
    END
  END d[295]
  PIN d[296]
    DIRECTION INPUT ;
    USE SIGNAL ;
    PORT
      LAYER M4 ;
        RECT  0 44.064 0.084 44.088 ;
    END
  END d[296]
  PIN d[297]
    DIRECTION INPUT ;
    USE SIGNAL ;
    PORT
      LAYER M4 ;
        RECT  0 44.16 0.084 44.184 ;
    END
  END d[297]
  PIN d[298]
    DIRECTION INPUT ;
    USE SIGNAL ;
    PORT
      LAYER M4 ;
        RECT  0 44.256 0.084 44.28 ;
    END
  END d[298]
  PIN d[299]
    DIRECTION INPUT ;
    USE SIGNAL ;
    PORT
      LAYER M4 ;
        RECT  0 44.352 0.084 44.376 ;
    END
  END d[299]
  PIN d[29]
    DIRECTION INPUT ;
    USE SIGNAL ;
    PORT
      LAYER M4 ;
        RECT  0 18.432 0.084 18.456 ;
    END
  END d[29]
  PIN d[2]
    DIRECTION INPUT ;
    USE SIGNAL ;
    PORT
      LAYER M4 ;
        RECT  0 15.84 0.084 15.864 ;
    END
  END d[2]
  PIN d[300]
    DIRECTION INPUT ;
    USE SIGNAL ;
    PORT
      LAYER M4 ;
        RECT  0 44.448 0.084 44.472 ;
    END
  END d[300]
  PIN d[301]
    DIRECTION INPUT ;
    USE SIGNAL ;
    PORT
      LAYER M4 ;
        RECT  0 44.544 0.084 44.568 ;
    END
  END d[301]
  PIN d[302]
    DIRECTION INPUT ;
    USE SIGNAL ;
    PORT
      LAYER M4 ;
        RECT  0 44.64 0.084 44.664 ;
    END
  END d[302]
  PIN d[303]
    DIRECTION INPUT ;
    USE SIGNAL ;
    PORT
      LAYER M4 ;
        RECT  0 44.736 0.084 44.76 ;
    END
  END d[303]
  PIN d[304]
    DIRECTION INPUT ;
    USE SIGNAL ;
    PORT
      LAYER M4 ;
        RECT  0 44.832 0.084 44.856 ;
    END
  END d[304]
  PIN d[305]
    DIRECTION INPUT ;
    USE SIGNAL ;
    PORT
      LAYER M4 ;
        RECT  0 44.928 0.084 44.952 ;
    END
  END d[305]
  PIN d[306]
    DIRECTION INPUT ;
    USE SIGNAL ;
    PORT
      LAYER M4 ;
        RECT  0 45.024 0.084 45.048 ;
    END
  END d[306]
  PIN d[307]
    DIRECTION INPUT ;
    USE SIGNAL ;
    PORT
      LAYER M4 ;
        RECT  0 45.12 0.084 45.144 ;
    END
  END d[307]
  PIN d[308]
    DIRECTION INPUT ;
    USE SIGNAL ;
    PORT
      LAYER M4 ;
        RECT  0 45.216 0.084 45.24 ;
    END
  END d[308]
  PIN d[309]
    DIRECTION INPUT ;
    USE SIGNAL ;
    PORT
      LAYER M4 ;
        RECT  0 45.312 0.084 45.336 ;
    END
  END d[309]
  PIN d[30]
    DIRECTION INPUT ;
    USE SIGNAL ;
    PORT
      LAYER M4 ;
        RECT  0 18.528 0.084 18.552 ;
    END
  END d[30]
  PIN d[310]
    DIRECTION INPUT ;
    USE SIGNAL ;
    PORT
      LAYER M4 ;
        RECT  0 45.408 0.084 45.432 ;
    END
  END d[310]
  PIN d[311]
    DIRECTION INPUT ;
    USE SIGNAL ;
    PORT
      LAYER M4 ;
        RECT  0 45.504 0.084 45.528 ;
    END
  END d[311]
  PIN d[312]
    DIRECTION INPUT ;
    USE SIGNAL ;
    PORT
      LAYER M4 ;
        RECT  0 45.6 0.084 45.624 ;
    END
  END d[312]
  PIN d[313]
    DIRECTION INPUT ;
    USE SIGNAL ;
    PORT
      LAYER M4 ;
        RECT  0 45.696 0.084 45.72 ;
    END
  END d[313]
  PIN d[314]
    DIRECTION INPUT ;
    USE SIGNAL ;
    PORT
      LAYER M4 ;
        RECT  0 45.792 0.084 45.816 ;
    END
  END d[314]
  PIN d[315]
    DIRECTION INPUT ;
    USE SIGNAL ;
    PORT
      LAYER M4 ;
        RECT  0 45.888 0.084 45.912 ;
    END
  END d[315]
  PIN d[316]
    DIRECTION INPUT ;
    USE SIGNAL ;
    PORT
      LAYER M4 ;
        RECT  0 45.984 0.084 46.008 ;
    END
  END d[316]
  PIN d[317]
    DIRECTION INPUT ;
    USE SIGNAL ;
    PORT
      LAYER M4 ;
        RECT  0 46.08 0.084 46.104 ;
    END
  END d[317]
  PIN d[318]
    DIRECTION INPUT ;
    USE SIGNAL ;
    PORT
      LAYER M4 ;
        RECT  0 46.176 0.084 46.2 ;
    END
  END d[318]
  PIN d[319]
    DIRECTION INPUT ;
    USE SIGNAL ;
    PORT
      LAYER M4 ;
        RECT  0 46.272 0.084 46.296 ;
    END
  END d[319]
  PIN d[31]
    DIRECTION INPUT ;
    USE SIGNAL ;
    PORT
      LAYER M4 ;
        RECT  0 18.624 0.084 18.648 ;
    END
  END d[31]
  PIN d[320]
    DIRECTION INPUT ;
    USE SIGNAL ;
    PORT
      LAYER M4 ;
        RECT  0 46.368 0.084 46.392 ;
    END
  END d[320]
  PIN d[321]
    DIRECTION INPUT ;
    USE SIGNAL ;
    PORT
      LAYER M4 ;
        RECT  0 46.464 0.084 46.488 ;
    END
  END d[321]
  PIN d[322]
    DIRECTION INPUT ;
    USE SIGNAL ;
    PORT
      LAYER M4 ;
        RECT  0 46.56 0.084 46.584 ;
    END
  END d[322]
  PIN d[323]
    DIRECTION INPUT ;
    USE SIGNAL ;
    PORT
      LAYER M4 ;
        RECT  0 46.656 0.084 46.68 ;
    END
  END d[323]
  PIN d[324]
    DIRECTION INPUT ;
    USE SIGNAL ;
    PORT
      LAYER M4 ;
        RECT  0 46.752 0.084 46.776 ;
    END
  END d[324]
  PIN d[325]
    DIRECTION INPUT ;
    USE SIGNAL ;
    PORT
      LAYER M4 ;
        RECT  0 46.848 0.084 46.872 ;
    END
  END d[325]
  PIN d[326]
    DIRECTION INPUT ;
    USE SIGNAL ;
    PORT
      LAYER M4 ;
        RECT  0 46.944 0.084 46.968 ;
    END
  END d[326]
  PIN d[327]
    DIRECTION INPUT ;
    USE SIGNAL ;
    PORT
      LAYER M4 ;
        RECT  0 47.04 0.084 47.064 ;
    END
  END d[327]
  PIN d[328]
    DIRECTION INPUT ;
    USE SIGNAL ;
    PORT
      LAYER M4 ;
        RECT  0 47.136 0.084 47.16 ;
    END
  END d[328]
  PIN d[329]
    DIRECTION INPUT ;
    USE SIGNAL ;
    PORT
      LAYER M4 ;
        RECT  0 47.232 0.084 47.256 ;
    END
  END d[329]
  PIN d[32]
    DIRECTION INPUT ;
    USE SIGNAL ;
    PORT
      LAYER M4 ;
        RECT  0 18.72 0.084 18.744 ;
    END
  END d[32]
  PIN d[330]
    DIRECTION INPUT ;
    USE SIGNAL ;
    PORT
      LAYER M4 ;
        RECT  0 47.328 0.084 47.352 ;
    END
  END d[330]
  PIN d[331]
    DIRECTION INPUT ;
    USE SIGNAL ;
    PORT
      LAYER M4 ;
        RECT  0 47.424 0.084 47.448 ;
    END
  END d[331]
  PIN d[332]
    DIRECTION INPUT ;
    USE SIGNAL ;
    PORT
      LAYER M4 ;
        RECT  0 47.52 0.084 47.544 ;
    END
  END d[332]
  PIN d[333]
    DIRECTION INPUT ;
    USE SIGNAL ;
    PORT
      LAYER M4 ;
        RECT  0 47.616 0.084 47.64 ;
    END
  END d[333]
  PIN d[334]
    DIRECTION INPUT ;
    USE SIGNAL ;
    PORT
      LAYER M4 ;
        RECT  0 47.712 0.084 47.736 ;
    END
  END d[334]
  PIN d[335]
    DIRECTION INPUT ;
    USE SIGNAL ;
    PORT
      LAYER M4 ;
        RECT  0 47.808 0.084 47.832 ;
    END
  END d[335]
  PIN d[336]
    DIRECTION INPUT ;
    USE SIGNAL ;
    PORT
      LAYER M4 ;
        RECT  0 47.904 0.084 47.928 ;
    END
  END d[336]
  PIN d[337]
    DIRECTION INPUT ;
    USE SIGNAL ;
    PORT
      LAYER M4 ;
        RECT  0 48 0.084 48.024 ;
    END
  END d[337]
  PIN d[338]
    DIRECTION INPUT ;
    USE SIGNAL ;
    PORT
      LAYER M4 ;
        RECT  0 48.096 0.084 48.12 ;
    END
  END d[338]
  PIN d[339]
    DIRECTION INPUT ;
    USE SIGNAL ;
    PORT
      LAYER M4 ;
        RECT  0 48.192 0.084 48.216 ;
    END
  END d[339]
  PIN d[33]
    DIRECTION INPUT ;
    USE SIGNAL ;
    PORT
      LAYER M4 ;
        RECT  0 18.816 0.084 18.84 ;
    END
  END d[33]
  PIN d[340]
    DIRECTION INPUT ;
    USE SIGNAL ;
    PORT
      LAYER M4 ;
        RECT  0 48.288 0.084 48.312 ;
    END
  END d[340]
  PIN d[341]
    DIRECTION INPUT ;
    USE SIGNAL ;
    PORT
      LAYER M4 ;
        RECT  0 48.384 0.084 48.408 ;
    END
  END d[341]
  PIN d[34]
    DIRECTION INPUT ;
    USE SIGNAL ;
    PORT
      LAYER M4 ;
        RECT  0 18.912 0.084 18.936 ;
    END
  END d[34]
  PIN d[35]
    DIRECTION INPUT ;
    USE SIGNAL ;
    PORT
      LAYER M4 ;
        RECT  0 19.008 0.084 19.032 ;
    END
  END d[35]
  PIN d[36]
    DIRECTION INPUT ;
    USE SIGNAL ;
    PORT
      LAYER M4 ;
        RECT  0 19.104 0.084 19.128 ;
    END
  END d[36]
  PIN d[37]
    DIRECTION INPUT ;
    USE SIGNAL ;
    PORT
      LAYER M4 ;
        RECT  0 19.2 0.084 19.224 ;
    END
  END d[37]
  PIN d[38]
    DIRECTION INPUT ;
    USE SIGNAL ;
    PORT
      LAYER M4 ;
        RECT  0 19.296 0.084 19.32 ;
    END
  END d[38]
  PIN d[39]
    DIRECTION INPUT ;
    USE SIGNAL ;
    PORT
      LAYER M4 ;
        RECT  0 19.392 0.084 19.416 ;
    END
  END d[39]
  PIN d[3]
    DIRECTION INPUT ;
    USE SIGNAL ;
    PORT
      LAYER M4 ;
        RECT  0 15.936 0.084 15.96 ;
    END
  END d[3]
  PIN d[40]
    DIRECTION INPUT ;
    USE SIGNAL ;
    PORT
      LAYER M4 ;
        RECT  0 19.488 0.084 19.512 ;
    END
  END d[40]
  PIN d[41]
    DIRECTION INPUT ;
    USE SIGNAL ;
    PORT
      LAYER M4 ;
        RECT  0 19.584 0.084 19.608 ;
    END
  END d[41]
  PIN d[42]
    DIRECTION INPUT ;
    USE SIGNAL ;
    PORT
      LAYER M4 ;
        RECT  0 19.68 0.084 19.704 ;
    END
  END d[42]
  PIN d[43]
    DIRECTION INPUT ;
    USE SIGNAL ;
    PORT
      LAYER M4 ;
        RECT  0 19.776 0.084 19.8 ;
    END
  END d[43]
  PIN d[44]
    DIRECTION INPUT ;
    USE SIGNAL ;
    PORT
      LAYER M4 ;
        RECT  0 19.872 0.084 19.896 ;
    END
  END d[44]
  PIN d[45]
    DIRECTION INPUT ;
    USE SIGNAL ;
    PORT
      LAYER M4 ;
        RECT  0 19.968 0.084 19.992 ;
    END
  END d[45]
  PIN d[46]
    DIRECTION INPUT ;
    USE SIGNAL ;
    PORT
      LAYER M4 ;
        RECT  0 20.064 0.084 20.088 ;
    END
  END d[46]
  PIN d[47]
    DIRECTION INPUT ;
    USE SIGNAL ;
    PORT
      LAYER M4 ;
        RECT  0 20.16 0.084 20.184 ;
    END
  END d[47]
  PIN d[48]
    DIRECTION INPUT ;
    USE SIGNAL ;
    PORT
      LAYER M4 ;
        RECT  0 20.256 0.084 20.28 ;
    END
  END d[48]
  PIN d[49]
    DIRECTION INPUT ;
    USE SIGNAL ;
    PORT
      LAYER M4 ;
        RECT  0 20.352 0.084 20.376 ;
    END
  END d[49]
  PIN d[4]
    DIRECTION INPUT ;
    USE SIGNAL ;
    PORT
      LAYER M4 ;
        RECT  0 16.032 0.084 16.056 ;
    END
  END d[4]
  PIN d[50]
    DIRECTION INPUT ;
    USE SIGNAL ;
    PORT
      LAYER M4 ;
        RECT  0 20.448 0.084 20.472 ;
    END
  END d[50]
  PIN d[51]
    DIRECTION INPUT ;
    USE SIGNAL ;
    PORT
      LAYER M4 ;
        RECT  0 20.544 0.084 20.568 ;
    END
  END d[51]
  PIN d[52]
    DIRECTION INPUT ;
    USE SIGNAL ;
    PORT
      LAYER M4 ;
        RECT  0 20.64 0.084 20.664 ;
    END
  END d[52]
  PIN d[53]
    DIRECTION INPUT ;
    USE SIGNAL ;
    PORT
      LAYER M4 ;
        RECT  0 20.736 0.084 20.76 ;
    END
  END d[53]
  PIN d[54]
    DIRECTION INPUT ;
    USE SIGNAL ;
    PORT
      LAYER M4 ;
        RECT  0 20.832 0.084 20.856 ;
    END
  END d[54]
  PIN d[55]
    DIRECTION INPUT ;
    USE SIGNAL ;
    PORT
      LAYER M4 ;
        RECT  0 20.928 0.084 20.952 ;
    END
  END d[55]
  PIN d[56]
    DIRECTION INPUT ;
    USE SIGNAL ;
    PORT
      LAYER M4 ;
        RECT  0 21.024 0.084 21.048 ;
    END
  END d[56]
  PIN d[57]
    DIRECTION INPUT ;
    USE SIGNAL ;
    PORT
      LAYER M4 ;
        RECT  0 21.12 0.084 21.144 ;
    END
  END d[57]
  PIN d[58]
    DIRECTION INPUT ;
    USE SIGNAL ;
    PORT
      LAYER M4 ;
        RECT  0 21.216 0.084 21.24 ;
    END
  END d[58]
  PIN d[59]
    DIRECTION INPUT ;
    USE SIGNAL ;
    PORT
      LAYER M4 ;
        RECT  0 21.312 0.084 21.336 ;
    END
  END d[59]
  PIN d[5]
    DIRECTION INPUT ;
    USE SIGNAL ;
    PORT
      LAYER M4 ;
        RECT  0 16.128 0.084 16.152 ;
    END
  END d[5]
  PIN d[60]
    DIRECTION INPUT ;
    USE SIGNAL ;
    PORT
      LAYER M4 ;
        RECT  0 21.408 0.084 21.432 ;
    END
  END d[60]
  PIN d[61]
    DIRECTION INPUT ;
    USE SIGNAL ;
    PORT
      LAYER M4 ;
        RECT  0 21.504 0.084 21.528 ;
    END
  END d[61]
  PIN d[62]
    DIRECTION INPUT ;
    USE SIGNAL ;
    PORT
      LAYER M4 ;
        RECT  0 21.6 0.084 21.624 ;
    END
  END d[62]
  PIN d[63]
    DIRECTION INPUT ;
    USE SIGNAL ;
    PORT
      LAYER M4 ;
        RECT  0 21.696 0.084 21.72 ;
    END
  END d[63]
  PIN d[64]
    DIRECTION INPUT ;
    USE SIGNAL ;
    PORT
      LAYER M4 ;
        RECT  0 21.792 0.084 21.816 ;
    END
  END d[64]
  PIN d[65]
    DIRECTION INPUT ;
    USE SIGNAL ;
    PORT
      LAYER M4 ;
        RECT  0 21.888 0.084 21.912 ;
    END
  END d[65]
  PIN d[66]
    DIRECTION INPUT ;
    USE SIGNAL ;
    PORT
      LAYER M4 ;
        RECT  0 21.984 0.084 22.008 ;
    END
  END d[66]
  PIN d[67]
    DIRECTION INPUT ;
    USE SIGNAL ;
    PORT
      LAYER M4 ;
        RECT  0 22.08 0.084 22.104 ;
    END
  END d[67]
  PIN d[68]
    DIRECTION INPUT ;
    USE SIGNAL ;
    PORT
      LAYER M4 ;
        RECT  0 22.176 0.084 22.2 ;
    END
  END d[68]
  PIN d[69]
    DIRECTION INPUT ;
    USE SIGNAL ;
    PORT
      LAYER M4 ;
        RECT  0 22.272 0.084 22.296 ;
    END
  END d[69]
  PIN d[6]
    DIRECTION INPUT ;
    USE SIGNAL ;
    PORT
      LAYER M4 ;
        RECT  0 16.224 0.084 16.248 ;
    END
  END d[6]
  PIN d[70]
    DIRECTION INPUT ;
    USE SIGNAL ;
    PORT
      LAYER M4 ;
        RECT  0 22.368 0.084 22.392 ;
    END
  END d[70]
  PIN d[71]
    DIRECTION INPUT ;
    USE SIGNAL ;
    PORT
      LAYER M4 ;
        RECT  0 22.464 0.084 22.488 ;
    END
  END d[71]
  PIN d[72]
    DIRECTION INPUT ;
    USE SIGNAL ;
    PORT
      LAYER M4 ;
        RECT  0 22.56 0.084 22.584 ;
    END
  END d[72]
  PIN d[73]
    DIRECTION INPUT ;
    USE SIGNAL ;
    PORT
      LAYER M4 ;
        RECT  0 22.656 0.084 22.68 ;
    END
  END d[73]
  PIN d[74]
    DIRECTION INPUT ;
    USE SIGNAL ;
    PORT
      LAYER M4 ;
        RECT  0 22.752 0.084 22.776 ;
    END
  END d[74]
  PIN d[75]
    DIRECTION INPUT ;
    USE SIGNAL ;
    PORT
      LAYER M4 ;
        RECT  0 22.848 0.084 22.872 ;
    END
  END d[75]
  PIN d[76]
    DIRECTION INPUT ;
    USE SIGNAL ;
    PORT
      LAYER M4 ;
        RECT  0 22.944 0.084 22.968 ;
    END
  END d[76]
  PIN d[77]
    DIRECTION INPUT ;
    USE SIGNAL ;
    PORT
      LAYER M4 ;
        RECT  0 23.04 0.084 23.064 ;
    END
  END d[77]
  PIN d[78]
    DIRECTION INPUT ;
    USE SIGNAL ;
    PORT
      LAYER M4 ;
        RECT  0 23.136 0.084 23.16 ;
    END
  END d[78]
  PIN d[79]
    DIRECTION INPUT ;
    USE SIGNAL ;
    PORT
      LAYER M4 ;
        RECT  0 23.232 0.084 23.256 ;
    END
  END d[79]
  PIN d[7]
    DIRECTION INPUT ;
    USE SIGNAL ;
    PORT
      LAYER M4 ;
        RECT  0 16.32 0.084 16.344 ;
    END
  END d[7]
  PIN d[80]
    DIRECTION INPUT ;
    USE SIGNAL ;
    PORT
      LAYER M4 ;
        RECT  0 23.328 0.084 23.352 ;
    END
  END d[80]
  PIN d[81]
    DIRECTION INPUT ;
    USE SIGNAL ;
    PORT
      LAYER M4 ;
        RECT  0 23.424 0.084 23.448 ;
    END
  END d[81]
  PIN d[82]
    DIRECTION INPUT ;
    USE SIGNAL ;
    PORT
      LAYER M4 ;
        RECT  0 23.52 0.084 23.544 ;
    END
  END d[82]
  PIN d[83]
    DIRECTION INPUT ;
    USE SIGNAL ;
    PORT
      LAYER M4 ;
        RECT  0 23.616 0.084 23.64 ;
    END
  END d[83]
  PIN d[84]
    DIRECTION INPUT ;
    USE SIGNAL ;
    PORT
      LAYER M4 ;
        RECT  0 23.712 0.084 23.736 ;
    END
  END d[84]
  PIN d[85]
    DIRECTION INPUT ;
    USE SIGNAL ;
    PORT
      LAYER M4 ;
        RECT  0 23.808 0.084 23.832 ;
    END
  END d[85]
  PIN d[86]
    DIRECTION INPUT ;
    USE SIGNAL ;
    PORT
      LAYER M4 ;
        RECT  0 23.904 0.084 23.928 ;
    END
  END d[86]
  PIN d[87]
    DIRECTION INPUT ;
    USE SIGNAL ;
    PORT
      LAYER M4 ;
        RECT  0 24 0.084 24.024 ;
    END
  END d[87]
  PIN d[88]
    DIRECTION INPUT ;
    USE SIGNAL ;
    PORT
      LAYER M4 ;
        RECT  0 24.096 0.084 24.12 ;
    END
  END d[88]
  PIN d[89]
    DIRECTION INPUT ;
    USE SIGNAL ;
    PORT
      LAYER M4 ;
        RECT  0 24.192 0.084 24.216 ;
    END
  END d[89]
  PIN d[8]
    DIRECTION INPUT ;
    USE SIGNAL ;
    PORT
      LAYER M4 ;
        RECT  0 16.416 0.084 16.44 ;
    END
  END d[8]
  PIN d[90]
    DIRECTION INPUT ;
    USE SIGNAL ;
    PORT
      LAYER M4 ;
        RECT  0 24.288 0.084 24.312 ;
    END
  END d[90]
  PIN d[91]
    DIRECTION INPUT ;
    USE SIGNAL ;
    PORT
      LAYER M4 ;
        RECT  0 24.384 0.084 24.408 ;
    END
  END d[91]
  PIN d[92]
    DIRECTION INPUT ;
    USE SIGNAL ;
    PORT
      LAYER M4 ;
        RECT  0 24.48 0.084 24.504 ;
    END
  END d[92]
  PIN d[93]
    DIRECTION INPUT ;
    USE SIGNAL ;
    PORT
      LAYER M4 ;
        RECT  0 24.576 0.084 24.6 ;
    END
  END d[93]
  PIN d[94]
    DIRECTION INPUT ;
    USE SIGNAL ;
    PORT
      LAYER M4 ;
        RECT  0 24.672 0.084 24.696 ;
    END
  END d[94]
  PIN d[95]
    DIRECTION INPUT ;
    USE SIGNAL ;
    PORT
      LAYER M4 ;
        RECT  0 24.768 0.084 24.792 ;
    END
  END d[95]
  PIN d[96]
    DIRECTION INPUT ;
    USE SIGNAL ;
    PORT
      LAYER M4 ;
        RECT  0 24.864 0.084 24.888 ;
    END
  END d[96]
  PIN d[97]
    DIRECTION INPUT ;
    USE SIGNAL ;
    PORT
      LAYER M4 ;
        RECT  0 24.96 0.084 24.984 ;
    END
  END d[97]
  PIN d[98]
    DIRECTION INPUT ;
    USE SIGNAL ;
    PORT
      LAYER M4 ;
        RECT  0 25.056 0.084 25.08 ;
    END
  END d[98]
  PIN d[99]
    DIRECTION INPUT ;
    USE SIGNAL ;
    PORT
      LAYER M4 ;
        RECT  0 25.152 0.084 25.176 ;
    END
  END d[99]
  PIN d[9]
    DIRECTION INPUT ;
    USE SIGNAL ;
    PORT
      LAYER M4 ;
        RECT  0 16.512 0.084 16.536 ;
    END
  END d[9]
  PIN q[0]
    DIRECTION OUTPUT ;
    USE SIGNAL ;
    PORT
      LAYER M4 ;
        RECT  769.916 15.552 770 15.576 ;
    END
  END q[0]
  PIN q[100]
    DIRECTION OUTPUT ;
    USE SIGNAL ;
    PORT
      LAYER M4 ;
        RECT  769.916 25.152 770 25.176 ;
    END
  END q[100]
  PIN q[101]
    DIRECTION OUTPUT ;
    USE SIGNAL ;
    PORT
      LAYER M4 ;
        RECT  769.916 25.248 770 25.272 ;
    END
  END q[101]
  PIN q[102]
    DIRECTION OUTPUT ;
    USE SIGNAL ;
    PORT
      LAYER M4 ;
        RECT  769.916 25.344 770 25.368 ;
    END
  END q[102]
  PIN q[103]
    DIRECTION OUTPUT ;
    USE SIGNAL ;
    PORT
      LAYER M4 ;
        RECT  769.916 25.44 770 25.464 ;
    END
  END q[103]
  PIN q[104]
    DIRECTION OUTPUT ;
    USE SIGNAL ;
    PORT
      LAYER M4 ;
        RECT  769.916 25.536 770 25.56 ;
    END
  END q[104]
  PIN q[105]
    DIRECTION OUTPUT ;
    USE SIGNAL ;
    PORT
      LAYER M4 ;
        RECT  769.916 25.632 770 25.656 ;
    END
  END q[105]
  PIN q[106]
    DIRECTION OUTPUT ;
    USE SIGNAL ;
    PORT
      LAYER M4 ;
        RECT  769.916 25.728 770 25.752 ;
    END
  END q[106]
  PIN q[107]
    DIRECTION OUTPUT ;
    USE SIGNAL ;
    PORT
      LAYER M4 ;
        RECT  769.916 25.824 770 25.848 ;
    END
  END q[107]
  PIN q[108]
    DIRECTION OUTPUT ;
    USE SIGNAL ;
    PORT
      LAYER M4 ;
        RECT  769.916 25.92 770 25.944 ;
    END
  END q[108]
  PIN q[109]
    DIRECTION OUTPUT ;
    USE SIGNAL ;
    PORT
      LAYER M4 ;
        RECT  769.916 26.016 770 26.04 ;
    END
  END q[109]
  PIN q[10]
    DIRECTION OUTPUT ;
    USE SIGNAL ;
    PORT
      LAYER M4 ;
        RECT  769.916 16.512 770 16.536 ;
    END
  END q[10]
  PIN q[110]
    DIRECTION OUTPUT ;
    USE SIGNAL ;
    PORT
      LAYER M4 ;
        RECT  769.916 26.112 770 26.136 ;
    END
  END q[110]
  PIN q[111]
    DIRECTION OUTPUT ;
    USE SIGNAL ;
    PORT
      LAYER M4 ;
        RECT  769.916 26.208 770 26.232 ;
    END
  END q[111]
  PIN q[112]
    DIRECTION OUTPUT ;
    USE SIGNAL ;
    PORT
      LAYER M4 ;
        RECT  769.916 26.304 770 26.328 ;
    END
  END q[112]
  PIN q[113]
    DIRECTION OUTPUT ;
    USE SIGNAL ;
    PORT
      LAYER M4 ;
        RECT  769.916 26.4 770 26.424 ;
    END
  END q[113]
  PIN q[114]
    DIRECTION OUTPUT ;
    USE SIGNAL ;
    PORT
      LAYER M4 ;
        RECT  769.916 26.496 770 26.52 ;
    END
  END q[114]
  PIN q[115]
    DIRECTION OUTPUT ;
    USE SIGNAL ;
    PORT
      LAYER M4 ;
        RECT  769.916 26.592 770 26.616 ;
    END
  END q[115]
  PIN q[116]
    DIRECTION OUTPUT ;
    USE SIGNAL ;
    PORT
      LAYER M4 ;
        RECT  769.916 26.688 770 26.712 ;
    END
  END q[116]
  PIN q[117]
    DIRECTION OUTPUT ;
    USE SIGNAL ;
    PORT
      LAYER M4 ;
        RECT  769.916 26.784 770 26.808 ;
    END
  END q[117]
  PIN q[118]
    DIRECTION OUTPUT ;
    USE SIGNAL ;
    PORT
      LAYER M4 ;
        RECT  769.916 26.88 770 26.904 ;
    END
  END q[118]
  PIN q[119]
    DIRECTION OUTPUT ;
    USE SIGNAL ;
    PORT
      LAYER M4 ;
        RECT  769.916 26.976 770 27 ;
    END
  END q[119]
  PIN q[11]
    DIRECTION OUTPUT ;
    USE SIGNAL ;
    PORT
      LAYER M4 ;
        RECT  769.916 16.608 770 16.632 ;
    END
  END q[11]
  PIN q[120]
    DIRECTION OUTPUT ;
    USE SIGNAL ;
    PORT
      LAYER M4 ;
        RECT  769.916 27.072 770 27.096 ;
    END
  END q[120]
  PIN q[121]
    DIRECTION OUTPUT ;
    USE SIGNAL ;
    PORT
      LAYER M4 ;
        RECT  769.916 27.168 770 27.192 ;
    END
  END q[121]
  PIN q[122]
    DIRECTION OUTPUT ;
    USE SIGNAL ;
    PORT
      LAYER M4 ;
        RECT  769.916 27.264 770 27.288 ;
    END
  END q[122]
  PIN q[123]
    DIRECTION OUTPUT ;
    USE SIGNAL ;
    PORT
      LAYER M4 ;
        RECT  769.916 27.36 770 27.384 ;
    END
  END q[123]
  PIN q[124]
    DIRECTION OUTPUT ;
    USE SIGNAL ;
    PORT
      LAYER M4 ;
        RECT  769.916 27.456 770 27.48 ;
    END
  END q[124]
  PIN q[125]
    DIRECTION OUTPUT ;
    USE SIGNAL ;
    PORT
      LAYER M4 ;
        RECT  769.916 27.552 770 27.576 ;
    END
  END q[125]
  PIN q[126]
    DIRECTION OUTPUT ;
    USE SIGNAL ;
    PORT
      LAYER M4 ;
        RECT  769.916 27.648 770 27.672 ;
    END
  END q[126]
  PIN q[127]
    DIRECTION OUTPUT ;
    USE SIGNAL ;
    PORT
      LAYER M4 ;
        RECT  769.916 27.744 770 27.768 ;
    END
  END q[127]
  PIN q[128]
    DIRECTION OUTPUT ;
    USE SIGNAL ;
    PORT
      LAYER M4 ;
        RECT  769.916 27.84 770 27.864 ;
    END
  END q[128]
  PIN q[129]
    DIRECTION OUTPUT ;
    USE SIGNAL ;
    PORT
      LAYER M4 ;
        RECT  769.916 27.936 770 27.96 ;
    END
  END q[129]
  PIN q[12]
    DIRECTION OUTPUT ;
    USE SIGNAL ;
    PORT
      LAYER M4 ;
        RECT  769.916 16.704 770 16.728 ;
    END
  END q[12]
  PIN q[130]
    DIRECTION OUTPUT ;
    USE SIGNAL ;
    PORT
      LAYER M4 ;
        RECT  769.916 28.032 770 28.056 ;
    END
  END q[130]
  PIN q[131]
    DIRECTION OUTPUT ;
    USE SIGNAL ;
    PORT
      LAYER M4 ;
        RECT  769.916 28.128 770 28.152 ;
    END
  END q[131]
  PIN q[132]
    DIRECTION OUTPUT ;
    USE SIGNAL ;
    PORT
      LAYER M4 ;
        RECT  769.916 28.224 770 28.248 ;
    END
  END q[132]
  PIN q[133]
    DIRECTION OUTPUT ;
    USE SIGNAL ;
    PORT
      LAYER M4 ;
        RECT  769.916 28.32 770 28.344 ;
    END
  END q[133]
  PIN q[134]
    DIRECTION OUTPUT ;
    USE SIGNAL ;
    PORT
      LAYER M4 ;
        RECT  769.916 28.416 770 28.44 ;
    END
  END q[134]
  PIN q[135]
    DIRECTION OUTPUT ;
    USE SIGNAL ;
    PORT
      LAYER M4 ;
        RECT  769.916 28.512 770 28.536 ;
    END
  END q[135]
  PIN q[136]
    DIRECTION OUTPUT ;
    USE SIGNAL ;
    PORT
      LAYER M4 ;
        RECT  769.916 28.608 770 28.632 ;
    END
  END q[136]
  PIN q[137]
    DIRECTION OUTPUT ;
    USE SIGNAL ;
    PORT
      LAYER M4 ;
        RECT  769.916 28.704 770 28.728 ;
    END
  END q[137]
  PIN q[138]
    DIRECTION OUTPUT ;
    USE SIGNAL ;
    PORT
      LAYER M4 ;
        RECT  769.916 28.8 770 28.824 ;
    END
  END q[138]
  PIN q[139]
    DIRECTION OUTPUT ;
    USE SIGNAL ;
    PORT
      LAYER M4 ;
        RECT  769.916 28.896 770 28.92 ;
    END
  END q[139]
  PIN q[13]
    DIRECTION OUTPUT ;
    USE SIGNAL ;
    PORT
      LAYER M4 ;
        RECT  769.916 16.8 770 16.824 ;
    END
  END q[13]
  PIN q[140]
    DIRECTION OUTPUT ;
    USE SIGNAL ;
    PORT
      LAYER M4 ;
        RECT  769.916 28.992 770 29.016 ;
    END
  END q[140]
  PIN q[141]
    DIRECTION OUTPUT ;
    USE SIGNAL ;
    PORT
      LAYER M4 ;
        RECT  769.916 29.088 770 29.112 ;
    END
  END q[141]
  PIN q[142]
    DIRECTION OUTPUT ;
    USE SIGNAL ;
    PORT
      LAYER M4 ;
        RECT  769.916 29.184 770 29.208 ;
    END
  END q[142]
  PIN q[143]
    DIRECTION OUTPUT ;
    USE SIGNAL ;
    PORT
      LAYER M4 ;
        RECT  769.916 29.28 770 29.304 ;
    END
  END q[143]
  PIN q[144]
    DIRECTION OUTPUT ;
    USE SIGNAL ;
    PORT
      LAYER M4 ;
        RECT  769.916 29.376 770 29.4 ;
    END
  END q[144]
  PIN q[145]
    DIRECTION OUTPUT ;
    USE SIGNAL ;
    PORT
      LAYER M4 ;
        RECT  769.916 29.472 770 29.496 ;
    END
  END q[145]
  PIN q[146]
    DIRECTION OUTPUT ;
    USE SIGNAL ;
    PORT
      LAYER M4 ;
        RECT  769.916 29.568 770 29.592 ;
    END
  END q[146]
  PIN q[147]
    DIRECTION OUTPUT ;
    USE SIGNAL ;
    PORT
      LAYER M4 ;
        RECT  769.916 29.664 770 29.688 ;
    END
  END q[147]
  PIN q[148]
    DIRECTION OUTPUT ;
    USE SIGNAL ;
    PORT
      LAYER M4 ;
        RECT  769.916 29.76 770 29.784 ;
    END
  END q[148]
  PIN q[149]
    DIRECTION OUTPUT ;
    USE SIGNAL ;
    PORT
      LAYER M4 ;
        RECT  769.916 29.856 770 29.88 ;
    END
  END q[149]
  PIN q[14]
    DIRECTION OUTPUT ;
    USE SIGNAL ;
    PORT
      LAYER M4 ;
        RECT  769.916 16.896 770 16.92 ;
    END
  END q[14]
  PIN q[150]
    DIRECTION OUTPUT ;
    USE SIGNAL ;
    PORT
      LAYER M4 ;
        RECT  769.916 29.952 770 29.976 ;
    END
  END q[150]
  PIN q[151]
    DIRECTION OUTPUT ;
    USE SIGNAL ;
    PORT
      LAYER M4 ;
        RECT  769.916 30.048 770 30.072 ;
    END
  END q[151]
  PIN q[152]
    DIRECTION OUTPUT ;
    USE SIGNAL ;
    PORT
      LAYER M4 ;
        RECT  769.916 30.144 770 30.168 ;
    END
  END q[152]
  PIN q[153]
    DIRECTION OUTPUT ;
    USE SIGNAL ;
    PORT
      LAYER M4 ;
        RECT  769.916 30.24 770 30.264 ;
    END
  END q[153]
  PIN q[154]
    DIRECTION OUTPUT ;
    USE SIGNAL ;
    PORT
      LAYER M4 ;
        RECT  769.916 30.336 770 30.36 ;
    END
  END q[154]
  PIN q[155]
    DIRECTION OUTPUT ;
    USE SIGNAL ;
    PORT
      LAYER M4 ;
        RECT  769.916 30.432 770 30.456 ;
    END
  END q[155]
  PIN q[156]
    DIRECTION OUTPUT ;
    USE SIGNAL ;
    PORT
      LAYER M4 ;
        RECT  769.916 30.528 770 30.552 ;
    END
  END q[156]
  PIN q[157]
    DIRECTION OUTPUT ;
    USE SIGNAL ;
    PORT
      LAYER M4 ;
        RECT  769.916 30.624 770 30.648 ;
    END
  END q[157]
  PIN q[158]
    DIRECTION OUTPUT ;
    USE SIGNAL ;
    PORT
      LAYER M4 ;
        RECT  769.916 30.72 770 30.744 ;
    END
  END q[158]
  PIN q[159]
    DIRECTION OUTPUT ;
    USE SIGNAL ;
    PORT
      LAYER M4 ;
        RECT  769.916 30.816 770 30.84 ;
    END
  END q[159]
  PIN q[15]
    DIRECTION OUTPUT ;
    USE SIGNAL ;
    PORT
      LAYER M4 ;
        RECT  769.916 16.992 770 17.016 ;
    END
  END q[15]
  PIN q[160]
    DIRECTION OUTPUT ;
    USE SIGNAL ;
    PORT
      LAYER M4 ;
        RECT  769.916 30.912 770 30.936 ;
    END
  END q[160]
  PIN q[161]
    DIRECTION OUTPUT ;
    USE SIGNAL ;
    PORT
      LAYER M4 ;
        RECT  769.916 31.008 770 31.032 ;
    END
  END q[161]
  PIN q[162]
    DIRECTION OUTPUT ;
    USE SIGNAL ;
    PORT
      LAYER M4 ;
        RECT  769.916 31.104 770 31.128 ;
    END
  END q[162]
  PIN q[163]
    DIRECTION OUTPUT ;
    USE SIGNAL ;
    PORT
      LAYER M4 ;
        RECT  769.916 31.2 770 31.224 ;
    END
  END q[163]
  PIN q[164]
    DIRECTION OUTPUT ;
    USE SIGNAL ;
    PORT
      LAYER M4 ;
        RECT  769.916 31.296 770 31.32 ;
    END
  END q[164]
  PIN q[165]
    DIRECTION OUTPUT ;
    USE SIGNAL ;
    PORT
      LAYER M4 ;
        RECT  769.916 31.392 770 31.416 ;
    END
  END q[165]
  PIN q[166]
    DIRECTION OUTPUT ;
    USE SIGNAL ;
    PORT
      LAYER M4 ;
        RECT  769.916 31.488 770 31.512 ;
    END
  END q[166]
  PIN q[167]
    DIRECTION OUTPUT ;
    USE SIGNAL ;
    PORT
      LAYER M4 ;
        RECT  769.916 31.584 770 31.608 ;
    END
  END q[167]
  PIN q[168]
    DIRECTION OUTPUT ;
    USE SIGNAL ;
    PORT
      LAYER M4 ;
        RECT  769.916 31.68 770 31.704 ;
    END
  END q[168]
  PIN q[169]
    DIRECTION OUTPUT ;
    USE SIGNAL ;
    PORT
      LAYER M4 ;
        RECT  769.916 31.776 770 31.8 ;
    END
  END q[169]
  PIN q[16]
    DIRECTION OUTPUT ;
    USE SIGNAL ;
    PORT
      LAYER M4 ;
        RECT  769.916 17.088 770 17.112 ;
    END
  END q[16]
  PIN q[170]
    DIRECTION OUTPUT ;
    USE SIGNAL ;
    PORT
      LAYER M4 ;
        RECT  769.916 31.872 770 31.896 ;
    END
  END q[170]
  PIN q[171]
    DIRECTION OUTPUT ;
    USE SIGNAL ;
    PORT
      LAYER M4 ;
        RECT  769.916 31.968 770 31.992 ;
    END
  END q[171]
  PIN q[172]
    DIRECTION OUTPUT ;
    USE SIGNAL ;
    PORT
      LAYER M4 ;
        RECT  769.916 32.064 770 32.088 ;
    END
  END q[172]
  PIN q[173]
    DIRECTION OUTPUT ;
    USE SIGNAL ;
    PORT
      LAYER M4 ;
        RECT  769.916 32.16 770 32.184 ;
    END
  END q[173]
  PIN q[174]
    DIRECTION OUTPUT ;
    USE SIGNAL ;
    PORT
      LAYER M4 ;
        RECT  769.916 32.256 770 32.28 ;
    END
  END q[174]
  PIN q[175]
    DIRECTION OUTPUT ;
    USE SIGNAL ;
    PORT
      LAYER M4 ;
        RECT  769.916 32.352 770 32.376 ;
    END
  END q[175]
  PIN q[176]
    DIRECTION OUTPUT ;
    USE SIGNAL ;
    PORT
      LAYER M4 ;
        RECT  769.916 32.448 770 32.472 ;
    END
  END q[176]
  PIN q[177]
    DIRECTION OUTPUT ;
    USE SIGNAL ;
    PORT
      LAYER M4 ;
        RECT  769.916 32.544 770 32.568 ;
    END
  END q[177]
  PIN q[178]
    DIRECTION OUTPUT ;
    USE SIGNAL ;
    PORT
      LAYER M4 ;
        RECT  769.916 32.64 770 32.664 ;
    END
  END q[178]
  PIN q[179]
    DIRECTION OUTPUT ;
    USE SIGNAL ;
    PORT
      LAYER M4 ;
        RECT  769.916 32.736 770 32.76 ;
    END
  END q[179]
  PIN q[17]
    DIRECTION OUTPUT ;
    USE SIGNAL ;
    PORT
      LAYER M4 ;
        RECT  769.916 17.184 770 17.208 ;
    END
  END q[17]
  PIN q[180]
    DIRECTION OUTPUT ;
    USE SIGNAL ;
    PORT
      LAYER M4 ;
        RECT  769.916 32.832 770 32.856 ;
    END
  END q[180]
  PIN q[181]
    DIRECTION OUTPUT ;
    USE SIGNAL ;
    PORT
      LAYER M4 ;
        RECT  769.916 32.928 770 32.952 ;
    END
  END q[181]
  PIN q[182]
    DIRECTION OUTPUT ;
    USE SIGNAL ;
    PORT
      LAYER M4 ;
        RECT  769.916 33.024 770 33.048 ;
    END
  END q[182]
  PIN q[183]
    DIRECTION OUTPUT ;
    USE SIGNAL ;
    PORT
      LAYER M4 ;
        RECT  769.916 33.12 770 33.144 ;
    END
  END q[183]
  PIN q[184]
    DIRECTION OUTPUT ;
    USE SIGNAL ;
    PORT
      LAYER M4 ;
        RECT  769.916 33.216 770 33.24 ;
    END
  END q[184]
  PIN q[185]
    DIRECTION OUTPUT ;
    USE SIGNAL ;
    PORT
      LAYER M4 ;
        RECT  769.916 33.312 770 33.336 ;
    END
  END q[185]
  PIN q[186]
    DIRECTION OUTPUT ;
    USE SIGNAL ;
    PORT
      LAYER M4 ;
        RECT  769.916 33.408 770 33.432 ;
    END
  END q[186]
  PIN q[187]
    DIRECTION OUTPUT ;
    USE SIGNAL ;
    PORT
      LAYER M4 ;
        RECT  769.916 33.504 770 33.528 ;
    END
  END q[187]
  PIN q[188]
    DIRECTION OUTPUT ;
    USE SIGNAL ;
    PORT
      LAYER M4 ;
        RECT  769.916 33.6 770 33.624 ;
    END
  END q[188]
  PIN q[189]
    DIRECTION OUTPUT ;
    USE SIGNAL ;
    PORT
      LAYER M4 ;
        RECT  769.916 33.696 770 33.72 ;
    END
  END q[189]
  PIN q[18]
    DIRECTION OUTPUT ;
    USE SIGNAL ;
    PORT
      LAYER M4 ;
        RECT  769.916 17.28 770 17.304 ;
    END
  END q[18]
  PIN q[190]
    DIRECTION OUTPUT ;
    USE SIGNAL ;
    PORT
      LAYER M4 ;
        RECT  769.916 33.792 770 33.816 ;
    END
  END q[190]
  PIN q[191]
    DIRECTION OUTPUT ;
    USE SIGNAL ;
    PORT
      LAYER M4 ;
        RECT  769.916 33.888 770 33.912 ;
    END
  END q[191]
  PIN q[192]
    DIRECTION OUTPUT ;
    USE SIGNAL ;
    PORT
      LAYER M4 ;
        RECT  769.916 33.984 770 34.008 ;
    END
  END q[192]
  PIN q[193]
    DIRECTION OUTPUT ;
    USE SIGNAL ;
    PORT
      LAYER M4 ;
        RECT  769.916 34.08 770 34.104 ;
    END
  END q[193]
  PIN q[194]
    DIRECTION OUTPUT ;
    USE SIGNAL ;
    PORT
      LAYER M4 ;
        RECT  769.916 34.176 770 34.2 ;
    END
  END q[194]
  PIN q[195]
    DIRECTION OUTPUT ;
    USE SIGNAL ;
    PORT
      LAYER M4 ;
        RECT  769.916 34.272 770 34.296 ;
    END
  END q[195]
  PIN q[196]
    DIRECTION OUTPUT ;
    USE SIGNAL ;
    PORT
      LAYER M4 ;
        RECT  769.916 34.368 770 34.392 ;
    END
  END q[196]
  PIN q[197]
    DIRECTION OUTPUT ;
    USE SIGNAL ;
    PORT
      LAYER M4 ;
        RECT  769.916 34.464 770 34.488 ;
    END
  END q[197]
  PIN q[198]
    DIRECTION OUTPUT ;
    USE SIGNAL ;
    PORT
      LAYER M4 ;
        RECT  769.916 34.56 770 34.584 ;
    END
  END q[198]
  PIN q[199]
    DIRECTION OUTPUT ;
    USE SIGNAL ;
    PORT
      LAYER M4 ;
        RECT  769.916 34.656 770 34.68 ;
    END
  END q[199]
  PIN q[19]
    DIRECTION OUTPUT ;
    USE SIGNAL ;
    PORT
      LAYER M4 ;
        RECT  769.916 17.376 770 17.4 ;
    END
  END q[19]
  PIN q[1]
    DIRECTION OUTPUT ;
    USE SIGNAL ;
    PORT
      LAYER M4 ;
        RECT  769.916 15.648 770 15.672 ;
    END
  END q[1]
  PIN q[200]
    DIRECTION OUTPUT ;
    USE SIGNAL ;
    PORT
      LAYER M4 ;
        RECT  769.916 34.752 770 34.776 ;
    END
  END q[200]
  PIN q[201]
    DIRECTION OUTPUT ;
    USE SIGNAL ;
    PORT
      LAYER M4 ;
        RECT  769.916 34.848 770 34.872 ;
    END
  END q[201]
  PIN q[202]
    DIRECTION OUTPUT ;
    USE SIGNAL ;
    PORT
      LAYER M4 ;
        RECT  769.916 34.944 770 34.968 ;
    END
  END q[202]
  PIN q[203]
    DIRECTION OUTPUT ;
    USE SIGNAL ;
    PORT
      LAYER M4 ;
        RECT  769.916 35.04 770 35.064 ;
    END
  END q[203]
  PIN q[204]
    DIRECTION OUTPUT ;
    USE SIGNAL ;
    PORT
      LAYER M4 ;
        RECT  769.916 35.136 770 35.16 ;
    END
  END q[204]
  PIN q[205]
    DIRECTION OUTPUT ;
    USE SIGNAL ;
    PORT
      LAYER M4 ;
        RECT  769.916 35.232 770 35.256 ;
    END
  END q[205]
  PIN q[206]
    DIRECTION OUTPUT ;
    USE SIGNAL ;
    PORT
      LAYER M4 ;
        RECT  769.916 35.328 770 35.352 ;
    END
  END q[206]
  PIN q[207]
    DIRECTION OUTPUT ;
    USE SIGNAL ;
    PORT
      LAYER M4 ;
        RECT  769.916 35.424 770 35.448 ;
    END
  END q[207]
  PIN q[208]
    DIRECTION OUTPUT ;
    USE SIGNAL ;
    PORT
      LAYER M4 ;
        RECT  769.916 35.52 770 35.544 ;
    END
  END q[208]
  PIN q[209]
    DIRECTION OUTPUT ;
    USE SIGNAL ;
    PORT
      LAYER M4 ;
        RECT  769.916 35.616 770 35.64 ;
    END
  END q[209]
  PIN q[20]
    DIRECTION OUTPUT ;
    USE SIGNAL ;
    PORT
      LAYER M4 ;
        RECT  769.916 17.472 770 17.496 ;
    END
  END q[20]
  PIN q[210]
    DIRECTION OUTPUT ;
    USE SIGNAL ;
    PORT
      LAYER M4 ;
        RECT  769.916 35.712 770 35.736 ;
    END
  END q[210]
  PIN q[211]
    DIRECTION OUTPUT ;
    USE SIGNAL ;
    PORT
      LAYER M4 ;
        RECT  769.916 35.808 770 35.832 ;
    END
  END q[211]
  PIN q[212]
    DIRECTION OUTPUT ;
    USE SIGNAL ;
    PORT
      LAYER M4 ;
        RECT  769.916 35.904 770 35.928 ;
    END
  END q[212]
  PIN q[213]
    DIRECTION OUTPUT ;
    USE SIGNAL ;
    PORT
      LAYER M4 ;
        RECT  769.916 36 770 36.024 ;
    END
  END q[213]
  PIN q[214]
    DIRECTION OUTPUT ;
    USE SIGNAL ;
    PORT
      LAYER M4 ;
        RECT  769.916 36.096 770 36.12 ;
    END
  END q[214]
  PIN q[215]
    DIRECTION OUTPUT ;
    USE SIGNAL ;
    PORT
      LAYER M4 ;
        RECT  769.916 36.192 770 36.216 ;
    END
  END q[215]
  PIN q[216]
    DIRECTION OUTPUT ;
    USE SIGNAL ;
    PORT
      LAYER M4 ;
        RECT  769.916 36.288 770 36.312 ;
    END
  END q[216]
  PIN q[217]
    DIRECTION OUTPUT ;
    USE SIGNAL ;
    PORT
      LAYER M4 ;
        RECT  769.916 36.384 770 36.408 ;
    END
  END q[217]
  PIN q[218]
    DIRECTION OUTPUT ;
    USE SIGNAL ;
    PORT
      LAYER M4 ;
        RECT  769.916 36.48 770 36.504 ;
    END
  END q[218]
  PIN q[219]
    DIRECTION OUTPUT ;
    USE SIGNAL ;
    PORT
      LAYER M4 ;
        RECT  769.916 36.576 770 36.6 ;
    END
  END q[219]
  PIN q[21]
    DIRECTION OUTPUT ;
    USE SIGNAL ;
    PORT
      LAYER M4 ;
        RECT  769.916 17.568 770 17.592 ;
    END
  END q[21]
  PIN q[220]
    DIRECTION OUTPUT ;
    USE SIGNAL ;
    PORT
      LAYER M4 ;
        RECT  769.916 36.672 770 36.696 ;
    END
  END q[220]
  PIN q[221]
    DIRECTION OUTPUT ;
    USE SIGNAL ;
    PORT
      LAYER M4 ;
        RECT  769.916 36.768 770 36.792 ;
    END
  END q[221]
  PIN q[222]
    DIRECTION OUTPUT ;
    USE SIGNAL ;
    PORT
      LAYER M4 ;
        RECT  769.916 36.864 770 36.888 ;
    END
  END q[222]
  PIN q[223]
    DIRECTION OUTPUT ;
    USE SIGNAL ;
    PORT
      LAYER M4 ;
        RECT  769.916 36.96 770 36.984 ;
    END
  END q[223]
  PIN q[224]
    DIRECTION OUTPUT ;
    USE SIGNAL ;
    PORT
      LAYER M4 ;
        RECT  769.916 37.056 770 37.08 ;
    END
  END q[224]
  PIN q[225]
    DIRECTION OUTPUT ;
    USE SIGNAL ;
    PORT
      LAYER M4 ;
        RECT  769.916 37.152 770 37.176 ;
    END
  END q[225]
  PIN q[226]
    DIRECTION OUTPUT ;
    USE SIGNAL ;
    PORT
      LAYER M4 ;
        RECT  769.916 37.248 770 37.272 ;
    END
  END q[226]
  PIN q[227]
    DIRECTION OUTPUT ;
    USE SIGNAL ;
    PORT
      LAYER M4 ;
        RECT  769.916 37.344 770 37.368 ;
    END
  END q[227]
  PIN q[228]
    DIRECTION OUTPUT ;
    USE SIGNAL ;
    PORT
      LAYER M4 ;
        RECT  769.916 37.44 770 37.464 ;
    END
  END q[228]
  PIN q[229]
    DIRECTION OUTPUT ;
    USE SIGNAL ;
    PORT
      LAYER M4 ;
        RECT  769.916 37.536 770 37.56 ;
    END
  END q[229]
  PIN q[22]
    DIRECTION OUTPUT ;
    USE SIGNAL ;
    PORT
      LAYER M4 ;
        RECT  769.916 17.664 770 17.688 ;
    END
  END q[22]
  PIN q[230]
    DIRECTION OUTPUT ;
    USE SIGNAL ;
    PORT
      LAYER M4 ;
        RECT  769.916 37.632 770 37.656 ;
    END
  END q[230]
  PIN q[231]
    DIRECTION OUTPUT ;
    USE SIGNAL ;
    PORT
      LAYER M4 ;
        RECT  769.916 37.728 770 37.752 ;
    END
  END q[231]
  PIN q[232]
    DIRECTION OUTPUT ;
    USE SIGNAL ;
    PORT
      LAYER M4 ;
        RECT  769.916 37.824 770 37.848 ;
    END
  END q[232]
  PIN q[233]
    DIRECTION OUTPUT ;
    USE SIGNAL ;
    PORT
      LAYER M4 ;
        RECT  769.916 37.92 770 37.944 ;
    END
  END q[233]
  PIN q[234]
    DIRECTION OUTPUT ;
    USE SIGNAL ;
    PORT
      LAYER M4 ;
        RECT  769.916 38.016 770 38.04 ;
    END
  END q[234]
  PIN q[235]
    DIRECTION OUTPUT ;
    USE SIGNAL ;
    PORT
      LAYER M4 ;
        RECT  769.916 38.112 770 38.136 ;
    END
  END q[235]
  PIN q[236]
    DIRECTION OUTPUT ;
    USE SIGNAL ;
    PORT
      LAYER M4 ;
        RECT  769.916 38.208 770 38.232 ;
    END
  END q[236]
  PIN q[237]
    DIRECTION OUTPUT ;
    USE SIGNAL ;
    PORT
      LAYER M4 ;
        RECT  769.916 38.304 770 38.328 ;
    END
  END q[237]
  PIN q[238]
    DIRECTION OUTPUT ;
    USE SIGNAL ;
    PORT
      LAYER M4 ;
        RECT  769.916 38.4 770 38.424 ;
    END
  END q[238]
  PIN q[239]
    DIRECTION OUTPUT ;
    USE SIGNAL ;
    PORT
      LAYER M4 ;
        RECT  769.916 38.496 770 38.52 ;
    END
  END q[239]
  PIN q[23]
    DIRECTION OUTPUT ;
    USE SIGNAL ;
    PORT
      LAYER M4 ;
        RECT  769.916 17.76 770 17.784 ;
    END
  END q[23]
  PIN q[240]
    DIRECTION OUTPUT ;
    USE SIGNAL ;
    PORT
      LAYER M4 ;
        RECT  769.916 38.592 770 38.616 ;
    END
  END q[240]
  PIN q[241]
    DIRECTION OUTPUT ;
    USE SIGNAL ;
    PORT
      LAYER M4 ;
        RECT  769.916 38.688 770 38.712 ;
    END
  END q[241]
  PIN q[242]
    DIRECTION OUTPUT ;
    USE SIGNAL ;
    PORT
      LAYER M4 ;
        RECT  769.916 38.784 770 38.808 ;
    END
  END q[242]
  PIN q[243]
    DIRECTION OUTPUT ;
    USE SIGNAL ;
    PORT
      LAYER M4 ;
        RECT  769.916 38.88 770 38.904 ;
    END
  END q[243]
  PIN q[244]
    DIRECTION OUTPUT ;
    USE SIGNAL ;
    PORT
      LAYER M4 ;
        RECT  769.916 38.976 770 39 ;
    END
  END q[244]
  PIN q[245]
    DIRECTION OUTPUT ;
    USE SIGNAL ;
    PORT
      LAYER M4 ;
        RECT  769.916 39.072 770 39.096 ;
    END
  END q[245]
  PIN q[246]
    DIRECTION OUTPUT ;
    USE SIGNAL ;
    PORT
      LAYER M4 ;
        RECT  769.916 39.168 770 39.192 ;
    END
  END q[246]
  PIN q[247]
    DIRECTION OUTPUT ;
    USE SIGNAL ;
    PORT
      LAYER M4 ;
        RECT  769.916 39.264 770 39.288 ;
    END
  END q[247]
  PIN q[248]
    DIRECTION OUTPUT ;
    USE SIGNAL ;
    PORT
      LAYER M4 ;
        RECT  769.916 39.36 770 39.384 ;
    END
  END q[248]
  PIN q[249]
    DIRECTION OUTPUT ;
    USE SIGNAL ;
    PORT
      LAYER M4 ;
        RECT  769.916 39.456 770 39.48 ;
    END
  END q[249]
  PIN q[24]
    DIRECTION OUTPUT ;
    USE SIGNAL ;
    PORT
      LAYER M4 ;
        RECT  769.916 17.856 770 17.88 ;
    END
  END q[24]
  PIN q[250]
    DIRECTION OUTPUT ;
    USE SIGNAL ;
    PORT
      LAYER M4 ;
        RECT  769.916 39.552 770 39.576 ;
    END
  END q[250]
  PIN q[251]
    DIRECTION OUTPUT ;
    USE SIGNAL ;
    PORT
      LAYER M4 ;
        RECT  769.916 39.648 770 39.672 ;
    END
  END q[251]
  PIN q[252]
    DIRECTION OUTPUT ;
    USE SIGNAL ;
    PORT
      LAYER M4 ;
        RECT  769.916 39.744 770 39.768 ;
    END
  END q[252]
  PIN q[253]
    DIRECTION OUTPUT ;
    USE SIGNAL ;
    PORT
      LAYER M4 ;
        RECT  769.916 39.84 770 39.864 ;
    END
  END q[253]
  PIN q[254]
    DIRECTION OUTPUT ;
    USE SIGNAL ;
    PORT
      LAYER M4 ;
        RECT  769.916 39.936 770 39.96 ;
    END
  END q[254]
  PIN q[255]
    DIRECTION OUTPUT ;
    USE SIGNAL ;
    PORT
      LAYER M4 ;
        RECT  769.916 40.032 770 40.056 ;
    END
  END q[255]
  PIN q[256]
    DIRECTION OUTPUT ;
    USE SIGNAL ;
    PORT
      LAYER M4 ;
        RECT  769.916 40.128 770 40.152 ;
    END
  END q[256]
  PIN q[257]
    DIRECTION OUTPUT ;
    USE SIGNAL ;
    PORT
      LAYER M4 ;
        RECT  769.916 40.224 770 40.248 ;
    END
  END q[257]
  PIN q[258]
    DIRECTION OUTPUT ;
    USE SIGNAL ;
    PORT
      LAYER M4 ;
        RECT  769.916 40.32 770 40.344 ;
    END
  END q[258]
  PIN q[259]
    DIRECTION OUTPUT ;
    USE SIGNAL ;
    PORT
      LAYER M4 ;
        RECT  769.916 40.416 770 40.44 ;
    END
  END q[259]
  PIN q[25]
    DIRECTION OUTPUT ;
    USE SIGNAL ;
    PORT
      LAYER M4 ;
        RECT  769.916 17.952 770 17.976 ;
    END
  END q[25]
  PIN q[260]
    DIRECTION OUTPUT ;
    USE SIGNAL ;
    PORT
      LAYER M4 ;
        RECT  769.916 40.512 770 40.536 ;
    END
  END q[260]
  PIN q[261]
    DIRECTION OUTPUT ;
    USE SIGNAL ;
    PORT
      LAYER M4 ;
        RECT  769.916 40.608 770 40.632 ;
    END
  END q[261]
  PIN q[262]
    DIRECTION OUTPUT ;
    USE SIGNAL ;
    PORT
      LAYER M4 ;
        RECT  769.916 40.704 770 40.728 ;
    END
  END q[262]
  PIN q[263]
    DIRECTION OUTPUT ;
    USE SIGNAL ;
    PORT
      LAYER M4 ;
        RECT  769.916 40.8 770 40.824 ;
    END
  END q[263]
  PIN q[264]
    DIRECTION OUTPUT ;
    USE SIGNAL ;
    PORT
      LAYER M4 ;
        RECT  769.916 40.896 770 40.92 ;
    END
  END q[264]
  PIN q[265]
    DIRECTION OUTPUT ;
    USE SIGNAL ;
    PORT
      LAYER M4 ;
        RECT  769.916 40.992 770 41.016 ;
    END
  END q[265]
  PIN q[266]
    DIRECTION OUTPUT ;
    USE SIGNAL ;
    PORT
      LAYER M4 ;
        RECT  769.916 41.088 770 41.112 ;
    END
  END q[266]
  PIN q[267]
    DIRECTION OUTPUT ;
    USE SIGNAL ;
    PORT
      LAYER M4 ;
        RECT  769.916 41.184 770 41.208 ;
    END
  END q[267]
  PIN q[268]
    DIRECTION OUTPUT ;
    USE SIGNAL ;
    PORT
      LAYER M4 ;
        RECT  769.916 41.28 770 41.304 ;
    END
  END q[268]
  PIN q[269]
    DIRECTION OUTPUT ;
    USE SIGNAL ;
    PORT
      LAYER M4 ;
        RECT  769.916 41.376 770 41.4 ;
    END
  END q[269]
  PIN q[26]
    DIRECTION OUTPUT ;
    USE SIGNAL ;
    PORT
      LAYER M4 ;
        RECT  769.916 18.048 770 18.072 ;
    END
  END q[26]
  PIN q[270]
    DIRECTION OUTPUT ;
    USE SIGNAL ;
    PORT
      LAYER M4 ;
        RECT  769.916 41.472 770 41.496 ;
    END
  END q[270]
  PIN q[271]
    DIRECTION OUTPUT ;
    USE SIGNAL ;
    PORT
      LAYER M4 ;
        RECT  769.916 41.568 770 41.592 ;
    END
  END q[271]
  PIN q[272]
    DIRECTION OUTPUT ;
    USE SIGNAL ;
    PORT
      LAYER M4 ;
        RECT  769.916 41.664 770 41.688 ;
    END
  END q[272]
  PIN q[273]
    DIRECTION OUTPUT ;
    USE SIGNAL ;
    PORT
      LAYER M4 ;
        RECT  769.916 41.76 770 41.784 ;
    END
  END q[273]
  PIN q[274]
    DIRECTION OUTPUT ;
    USE SIGNAL ;
    PORT
      LAYER M4 ;
        RECT  769.916 41.856 770 41.88 ;
    END
  END q[274]
  PIN q[275]
    DIRECTION OUTPUT ;
    USE SIGNAL ;
    PORT
      LAYER M4 ;
        RECT  769.916 41.952 770 41.976 ;
    END
  END q[275]
  PIN q[276]
    DIRECTION OUTPUT ;
    USE SIGNAL ;
    PORT
      LAYER M4 ;
        RECT  769.916 42.048 770 42.072 ;
    END
  END q[276]
  PIN q[277]
    DIRECTION OUTPUT ;
    USE SIGNAL ;
    PORT
      LAYER M4 ;
        RECT  769.916 42.144 770 42.168 ;
    END
  END q[277]
  PIN q[278]
    DIRECTION OUTPUT ;
    USE SIGNAL ;
    PORT
      LAYER M4 ;
        RECT  769.916 42.24 770 42.264 ;
    END
  END q[278]
  PIN q[279]
    DIRECTION OUTPUT ;
    USE SIGNAL ;
    PORT
      LAYER M4 ;
        RECT  769.916 42.336 770 42.36 ;
    END
  END q[279]
  PIN q[27]
    DIRECTION OUTPUT ;
    USE SIGNAL ;
    PORT
      LAYER M4 ;
        RECT  769.916 18.144 770 18.168 ;
    END
  END q[27]
  PIN q[280]
    DIRECTION OUTPUT ;
    USE SIGNAL ;
    PORT
      LAYER M4 ;
        RECT  769.916 42.432 770 42.456 ;
    END
  END q[280]
  PIN q[281]
    DIRECTION OUTPUT ;
    USE SIGNAL ;
    PORT
      LAYER M4 ;
        RECT  769.916 42.528 770 42.552 ;
    END
  END q[281]
  PIN q[282]
    DIRECTION OUTPUT ;
    USE SIGNAL ;
    PORT
      LAYER M4 ;
        RECT  769.916 42.624 770 42.648 ;
    END
  END q[282]
  PIN q[283]
    DIRECTION OUTPUT ;
    USE SIGNAL ;
    PORT
      LAYER M4 ;
        RECT  769.916 42.72 770 42.744 ;
    END
  END q[283]
  PIN q[284]
    DIRECTION OUTPUT ;
    USE SIGNAL ;
    PORT
      LAYER M4 ;
        RECT  769.916 42.816 770 42.84 ;
    END
  END q[284]
  PIN q[285]
    DIRECTION OUTPUT ;
    USE SIGNAL ;
    PORT
      LAYER M4 ;
        RECT  769.916 42.912 770 42.936 ;
    END
  END q[285]
  PIN q[286]
    DIRECTION OUTPUT ;
    USE SIGNAL ;
    PORT
      LAYER M4 ;
        RECT  769.916 43.008 770 43.032 ;
    END
  END q[286]
  PIN q[287]
    DIRECTION OUTPUT ;
    USE SIGNAL ;
    PORT
      LAYER M4 ;
        RECT  769.916 43.104 770 43.128 ;
    END
  END q[287]
  PIN q[288]
    DIRECTION OUTPUT ;
    USE SIGNAL ;
    PORT
      LAYER M4 ;
        RECT  769.916 43.2 770 43.224 ;
    END
  END q[288]
  PIN q[289]
    DIRECTION OUTPUT ;
    USE SIGNAL ;
    PORT
      LAYER M4 ;
        RECT  769.916 43.296 770 43.32 ;
    END
  END q[289]
  PIN q[28]
    DIRECTION OUTPUT ;
    USE SIGNAL ;
    PORT
      LAYER M4 ;
        RECT  769.916 18.24 770 18.264 ;
    END
  END q[28]
  PIN q[290]
    DIRECTION OUTPUT ;
    USE SIGNAL ;
    PORT
      LAYER M4 ;
        RECT  769.916 43.392 770 43.416 ;
    END
  END q[290]
  PIN q[291]
    DIRECTION OUTPUT ;
    USE SIGNAL ;
    PORT
      LAYER M4 ;
        RECT  769.916 43.488 770 43.512 ;
    END
  END q[291]
  PIN q[292]
    DIRECTION OUTPUT ;
    USE SIGNAL ;
    PORT
      LAYER M4 ;
        RECT  769.916 43.584 770 43.608 ;
    END
  END q[292]
  PIN q[293]
    DIRECTION OUTPUT ;
    USE SIGNAL ;
    PORT
      LAYER M4 ;
        RECT  769.916 43.68 770 43.704 ;
    END
  END q[293]
  PIN q[294]
    DIRECTION OUTPUT ;
    USE SIGNAL ;
    PORT
      LAYER M4 ;
        RECT  769.916 43.776 770 43.8 ;
    END
  END q[294]
  PIN q[295]
    DIRECTION OUTPUT ;
    USE SIGNAL ;
    PORT
      LAYER M4 ;
        RECT  769.916 43.872 770 43.896 ;
    END
  END q[295]
  PIN q[296]
    DIRECTION OUTPUT ;
    USE SIGNAL ;
    PORT
      LAYER M4 ;
        RECT  769.916 43.968 770 43.992 ;
    END
  END q[296]
  PIN q[297]
    DIRECTION OUTPUT ;
    USE SIGNAL ;
    PORT
      LAYER M4 ;
        RECT  769.916 44.064 770 44.088 ;
    END
  END q[297]
  PIN q[298]
    DIRECTION OUTPUT ;
    USE SIGNAL ;
    PORT
      LAYER M4 ;
        RECT  769.916 44.16 770 44.184 ;
    END
  END q[298]
  PIN q[299]
    DIRECTION OUTPUT ;
    USE SIGNAL ;
    PORT
      LAYER M4 ;
        RECT  769.916 44.256 770 44.28 ;
    END
  END q[299]
  PIN q[29]
    DIRECTION OUTPUT ;
    USE SIGNAL ;
    PORT
      LAYER M4 ;
        RECT  769.916 18.336 770 18.36 ;
    END
  END q[29]
  PIN q[2]
    DIRECTION OUTPUT ;
    USE SIGNAL ;
    PORT
      LAYER M4 ;
        RECT  769.916 15.744 770 15.768 ;
    END
  END q[2]
  PIN q[300]
    DIRECTION OUTPUT ;
    USE SIGNAL ;
    PORT
      LAYER M4 ;
        RECT  769.916 44.352 770 44.376 ;
    END
  END q[300]
  PIN q[301]
    DIRECTION OUTPUT ;
    USE SIGNAL ;
    PORT
      LAYER M4 ;
        RECT  769.916 44.448 770 44.472 ;
    END
  END q[301]
  PIN q[302]
    DIRECTION OUTPUT ;
    USE SIGNAL ;
    PORT
      LAYER M4 ;
        RECT  769.916 44.544 770 44.568 ;
    END
  END q[302]
  PIN q[303]
    DIRECTION OUTPUT ;
    USE SIGNAL ;
    PORT
      LAYER M4 ;
        RECT  769.916 44.64 770 44.664 ;
    END
  END q[303]
  PIN q[304]
    DIRECTION OUTPUT ;
    USE SIGNAL ;
    PORT
      LAYER M4 ;
        RECT  769.916 44.736 770 44.76 ;
    END
  END q[304]
  PIN q[305]
    DIRECTION OUTPUT ;
    USE SIGNAL ;
    PORT
      LAYER M4 ;
        RECT  769.916 44.832 770 44.856 ;
    END
  END q[305]
  PIN q[306]
    DIRECTION OUTPUT ;
    USE SIGNAL ;
    PORT
      LAYER M4 ;
        RECT  769.916 44.928 770 44.952 ;
    END
  END q[306]
  PIN q[307]
    DIRECTION OUTPUT ;
    USE SIGNAL ;
    PORT
      LAYER M4 ;
        RECT  769.916 45.024 770 45.048 ;
    END
  END q[307]
  PIN q[308]
    DIRECTION OUTPUT ;
    USE SIGNAL ;
    PORT
      LAYER M4 ;
        RECT  769.916 45.12 770 45.144 ;
    END
  END q[308]
  PIN q[309]
    DIRECTION OUTPUT ;
    USE SIGNAL ;
    PORT
      LAYER M4 ;
        RECT  769.916 45.216 770 45.24 ;
    END
  END q[309]
  PIN q[30]
    DIRECTION OUTPUT ;
    USE SIGNAL ;
    PORT
      LAYER M4 ;
        RECT  769.916 18.432 770 18.456 ;
    END
  END q[30]
  PIN q[310]
    DIRECTION OUTPUT ;
    USE SIGNAL ;
    PORT
      LAYER M4 ;
        RECT  769.916 45.312 770 45.336 ;
    END
  END q[310]
  PIN q[311]
    DIRECTION OUTPUT ;
    USE SIGNAL ;
    PORT
      LAYER M4 ;
        RECT  769.916 45.408 770 45.432 ;
    END
  END q[311]
  PIN q[312]
    DIRECTION OUTPUT ;
    USE SIGNAL ;
    PORT
      LAYER M4 ;
        RECT  769.916 45.504 770 45.528 ;
    END
  END q[312]
  PIN q[313]
    DIRECTION OUTPUT ;
    USE SIGNAL ;
    PORT
      LAYER M4 ;
        RECT  769.916 45.6 770 45.624 ;
    END
  END q[313]
  PIN q[314]
    DIRECTION OUTPUT ;
    USE SIGNAL ;
    PORT
      LAYER M4 ;
        RECT  769.916 45.696 770 45.72 ;
    END
  END q[314]
  PIN q[315]
    DIRECTION OUTPUT ;
    USE SIGNAL ;
    PORT
      LAYER M4 ;
        RECT  769.916 45.792 770 45.816 ;
    END
  END q[315]
  PIN q[316]
    DIRECTION OUTPUT ;
    USE SIGNAL ;
    PORT
      LAYER M4 ;
        RECT  769.916 45.888 770 45.912 ;
    END
  END q[316]
  PIN q[317]
    DIRECTION OUTPUT ;
    USE SIGNAL ;
    PORT
      LAYER M4 ;
        RECT  769.916 45.984 770 46.008 ;
    END
  END q[317]
  PIN q[318]
    DIRECTION OUTPUT ;
    USE SIGNAL ;
    PORT
      LAYER M4 ;
        RECT  769.916 46.08 770 46.104 ;
    END
  END q[318]
  PIN q[319]
    DIRECTION OUTPUT ;
    USE SIGNAL ;
    PORT
      LAYER M4 ;
        RECT  769.916 46.176 770 46.2 ;
    END
  END q[319]
  PIN q[31]
    DIRECTION OUTPUT ;
    USE SIGNAL ;
    PORT
      LAYER M4 ;
        RECT  769.916 18.528 770 18.552 ;
    END
  END q[31]
  PIN q[320]
    DIRECTION OUTPUT ;
    USE SIGNAL ;
    PORT
      LAYER M4 ;
        RECT  769.916 46.272 770 46.296 ;
    END
  END q[320]
  PIN q[321]
    DIRECTION OUTPUT ;
    USE SIGNAL ;
    PORT
      LAYER M4 ;
        RECT  769.916 46.368 770 46.392 ;
    END
  END q[321]
  PIN q[322]
    DIRECTION OUTPUT ;
    USE SIGNAL ;
    PORT
      LAYER M4 ;
        RECT  769.916 46.464 770 46.488 ;
    END
  END q[322]
  PIN q[323]
    DIRECTION OUTPUT ;
    USE SIGNAL ;
    PORT
      LAYER M4 ;
        RECT  769.916 46.56 770 46.584 ;
    END
  END q[323]
  PIN q[324]
    DIRECTION OUTPUT ;
    USE SIGNAL ;
    PORT
      LAYER M4 ;
        RECT  769.916 46.656 770 46.68 ;
    END
  END q[324]
  PIN q[325]
    DIRECTION OUTPUT ;
    USE SIGNAL ;
    PORT
      LAYER M4 ;
        RECT  769.916 46.752 770 46.776 ;
    END
  END q[325]
  PIN q[326]
    DIRECTION OUTPUT ;
    USE SIGNAL ;
    PORT
      LAYER M4 ;
        RECT  769.916 46.848 770 46.872 ;
    END
  END q[326]
  PIN q[327]
    DIRECTION OUTPUT ;
    USE SIGNAL ;
    PORT
      LAYER M4 ;
        RECT  769.916 46.944 770 46.968 ;
    END
  END q[327]
  PIN q[328]
    DIRECTION OUTPUT ;
    USE SIGNAL ;
    PORT
      LAYER M4 ;
        RECT  769.916 47.04 770 47.064 ;
    END
  END q[328]
  PIN q[329]
    DIRECTION OUTPUT ;
    USE SIGNAL ;
    PORT
      LAYER M4 ;
        RECT  769.916 47.136 770 47.16 ;
    END
  END q[329]
  PIN q[32]
    DIRECTION OUTPUT ;
    USE SIGNAL ;
    PORT
      LAYER M4 ;
        RECT  769.916 18.624 770 18.648 ;
    END
  END q[32]
  PIN q[330]
    DIRECTION OUTPUT ;
    USE SIGNAL ;
    PORT
      LAYER M4 ;
        RECT  769.916 47.232 770 47.256 ;
    END
  END q[330]
  PIN q[331]
    DIRECTION OUTPUT ;
    USE SIGNAL ;
    PORT
      LAYER M4 ;
        RECT  769.916 47.328 770 47.352 ;
    END
  END q[331]
  PIN q[332]
    DIRECTION OUTPUT ;
    USE SIGNAL ;
    PORT
      LAYER M4 ;
        RECT  769.916 47.424 770 47.448 ;
    END
  END q[332]
  PIN q[333]
    DIRECTION OUTPUT ;
    USE SIGNAL ;
    PORT
      LAYER M4 ;
        RECT  769.916 47.52 770 47.544 ;
    END
  END q[333]
  PIN q[334]
    DIRECTION OUTPUT ;
    USE SIGNAL ;
    PORT
      LAYER M4 ;
        RECT  769.916 47.616 770 47.64 ;
    END
  END q[334]
  PIN q[335]
    DIRECTION OUTPUT ;
    USE SIGNAL ;
    PORT
      LAYER M4 ;
        RECT  769.916 47.712 770 47.736 ;
    END
  END q[335]
  PIN q[336]
    DIRECTION OUTPUT ;
    USE SIGNAL ;
    PORT
      LAYER M4 ;
        RECT  769.916 47.808 770 47.832 ;
    END
  END q[336]
  PIN q[337]
    DIRECTION OUTPUT ;
    USE SIGNAL ;
    PORT
      LAYER M4 ;
        RECT  769.916 47.904 770 47.928 ;
    END
  END q[337]
  PIN q[338]
    DIRECTION OUTPUT ;
    USE SIGNAL ;
    PORT
      LAYER M4 ;
        RECT  769.916 48 770 48.024 ;
    END
  END q[338]
  PIN q[339]
    DIRECTION OUTPUT ;
    USE SIGNAL ;
    PORT
      LAYER M4 ;
        RECT  769.916 48.096 770 48.12 ;
    END
  END q[339]
  PIN q[33]
    DIRECTION OUTPUT ;
    USE SIGNAL ;
    PORT
      LAYER M4 ;
        RECT  769.916 18.72 770 18.744 ;
    END
  END q[33]
  PIN q[340]
    DIRECTION OUTPUT ;
    USE SIGNAL ;
    PORT
      LAYER M4 ;
        RECT  769.916 48.192 770 48.216 ;
    END
  END q[340]
  PIN q[341]
    DIRECTION OUTPUT ;
    USE SIGNAL ;
    PORT
      LAYER M4 ;
        RECT  769.916 48.288 770 48.312 ;
    END
  END q[341]
  PIN q[34]
    DIRECTION OUTPUT ;
    USE SIGNAL ;
    PORT
      LAYER M4 ;
        RECT  769.916 18.816 770 18.84 ;
    END
  END q[34]
  PIN q[35]
    DIRECTION OUTPUT ;
    USE SIGNAL ;
    PORT
      LAYER M4 ;
        RECT  769.916 18.912 770 18.936 ;
    END
  END q[35]
  PIN q[36]
    DIRECTION OUTPUT ;
    USE SIGNAL ;
    PORT
      LAYER M4 ;
        RECT  769.916 19.008 770 19.032 ;
    END
  END q[36]
  PIN q[37]
    DIRECTION OUTPUT ;
    USE SIGNAL ;
    PORT
      LAYER M4 ;
        RECT  769.916 19.104 770 19.128 ;
    END
  END q[37]
  PIN q[38]
    DIRECTION OUTPUT ;
    USE SIGNAL ;
    PORT
      LAYER M4 ;
        RECT  769.916 19.2 770 19.224 ;
    END
  END q[38]
  PIN q[39]
    DIRECTION OUTPUT ;
    USE SIGNAL ;
    PORT
      LAYER M4 ;
        RECT  769.916 19.296 770 19.32 ;
    END
  END q[39]
  PIN q[3]
    DIRECTION OUTPUT ;
    USE SIGNAL ;
    PORT
      LAYER M4 ;
        RECT  769.916 15.84 770 15.864 ;
    END
  END q[3]
  PIN q[40]
    DIRECTION OUTPUT ;
    USE SIGNAL ;
    PORT
      LAYER M4 ;
        RECT  769.916 19.392 770 19.416 ;
    END
  END q[40]
  PIN q[41]
    DIRECTION OUTPUT ;
    USE SIGNAL ;
    PORT
      LAYER M4 ;
        RECT  769.916 19.488 770 19.512 ;
    END
  END q[41]
  PIN q[42]
    DIRECTION OUTPUT ;
    USE SIGNAL ;
    PORT
      LAYER M4 ;
        RECT  769.916 19.584 770 19.608 ;
    END
  END q[42]
  PIN q[43]
    DIRECTION OUTPUT ;
    USE SIGNAL ;
    PORT
      LAYER M4 ;
        RECT  769.916 19.68 770 19.704 ;
    END
  END q[43]
  PIN q[44]
    DIRECTION OUTPUT ;
    USE SIGNAL ;
    PORT
      LAYER M4 ;
        RECT  769.916 19.776 770 19.8 ;
    END
  END q[44]
  PIN q[45]
    DIRECTION OUTPUT ;
    USE SIGNAL ;
    PORT
      LAYER M4 ;
        RECT  769.916 19.872 770 19.896 ;
    END
  END q[45]
  PIN q[46]
    DIRECTION OUTPUT ;
    USE SIGNAL ;
    PORT
      LAYER M4 ;
        RECT  769.916 19.968 770 19.992 ;
    END
  END q[46]
  PIN q[47]
    DIRECTION OUTPUT ;
    USE SIGNAL ;
    PORT
      LAYER M4 ;
        RECT  769.916 20.064 770 20.088 ;
    END
  END q[47]
  PIN q[48]
    DIRECTION OUTPUT ;
    USE SIGNAL ;
    PORT
      LAYER M4 ;
        RECT  769.916 20.16 770 20.184 ;
    END
  END q[48]
  PIN q[49]
    DIRECTION OUTPUT ;
    USE SIGNAL ;
    PORT
      LAYER M4 ;
        RECT  769.916 20.256 770 20.28 ;
    END
  END q[49]
  PIN q[4]
    DIRECTION OUTPUT ;
    USE SIGNAL ;
    PORT
      LAYER M4 ;
        RECT  769.916 15.936 770 15.96 ;
    END
  END q[4]
  PIN q[50]
    DIRECTION OUTPUT ;
    USE SIGNAL ;
    PORT
      LAYER M4 ;
        RECT  769.916 20.352 770 20.376 ;
    END
  END q[50]
  PIN q[51]
    DIRECTION OUTPUT ;
    USE SIGNAL ;
    PORT
      LAYER M4 ;
        RECT  769.916 20.448 770 20.472 ;
    END
  END q[51]
  PIN q[52]
    DIRECTION OUTPUT ;
    USE SIGNAL ;
    PORT
      LAYER M4 ;
        RECT  769.916 20.544 770 20.568 ;
    END
  END q[52]
  PIN q[53]
    DIRECTION OUTPUT ;
    USE SIGNAL ;
    PORT
      LAYER M4 ;
        RECT  769.916 20.64 770 20.664 ;
    END
  END q[53]
  PIN q[54]
    DIRECTION OUTPUT ;
    USE SIGNAL ;
    PORT
      LAYER M4 ;
        RECT  769.916 20.736 770 20.76 ;
    END
  END q[54]
  PIN q[55]
    DIRECTION OUTPUT ;
    USE SIGNAL ;
    PORT
      LAYER M4 ;
        RECT  769.916 20.832 770 20.856 ;
    END
  END q[55]
  PIN q[56]
    DIRECTION OUTPUT ;
    USE SIGNAL ;
    PORT
      LAYER M4 ;
        RECT  769.916 20.928 770 20.952 ;
    END
  END q[56]
  PIN q[57]
    DIRECTION OUTPUT ;
    USE SIGNAL ;
    PORT
      LAYER M4 ;
        RECT  769.916 21.024 770 21.048 ;
    END
  END q[57]
  PIN q[58]
    DIRECTION OUTPUT ;
    USE SIGNAL ;
    PORT
      LAYER M4 ;
        RECT  769.916 21.12 770 21.144 ;
    END
  END q[58]
  PIN q[59]
    DIRECTION OUTPUT ;
    USE SIGNAL ;
    PORT
      LAYER M4 ;
        RECT  769.916 21.216 770 21.24 ;
    END
  END q[59]
  PIN q[5]
    DIRECTION OUTPUT ;
    USE SIGNAL ;
    PORT
      LAYER M4 ;
        RECT  769.916 16.032 770 16.056 ;
    END
  END q[5]
  PIN q[60]
    DIRECTION OUTPUT ;
    USE SIGNAL ;
    PORT
      LAYER M4 ;
        RECT  769.916 21.312 770 21.336 ;
    END
  END q[60]
  PIN q[61]
    DIRECTION OUTPUT ;
    USE SIGNAL ;
    PORT
      LAYER M4 ;
        RECT  769.916 21.408 770 21.432 ;
    END
  END q[61]
  PIN q[62]
    DIRECTION OUTPUT ;
    USE SIGNAL ;
    PORT
      LAYER M4 ;
        RECT  769.916 21.504 770 21.528 ;
    END
  END q[62]
  PIN q[63]
    DIRECTION OUTPUT ;
    USE SIGNAL ;
    PORT
      LAYER M4 ;
        RECT  769.916 21.6 770 21.624 ;
    END
  END q[63]
  PIN q[64]
    DIRECTION OUTPUT ;
    USE SIGNAL ;
    PORT
      LAYER M4 ;
        RECT  769.916 21.696 770 21.72 ;
    END
  END q[64]
  PIN q[65]
    DIRECTION OUTPUT ;
    USE SIGNAL ;
    PORT
      LAYER M4 ;
        RECT  769.916 21.792 770 21.816 ;
    END
  END q[65]
  PIN q[66]
    DIRECTION OUTPUT ;
    USE SIGNAL ;
    PORT
      LAYER M4 ;
        RECT  769.916 21.888 770 21.912 ;
    END
  END q[66]
  PIN q[67]
    DIRECTION OUTPUT ;
    USE SIGNAL ;
    PORT
      LAYER M4 ;
        RECT  769.916 21.984 770 22.008 ;
    END
  END q[67]
  PIN q[68]
    DIRECTION OUTPUT ;
    USE SIGNAL ;
    PORT
      LAYER M4 ;
        RECT  769.916 22.08 770 22.104 ;
    END
  END q[68]
  PIN q[69]
    DIRECTION OUTPUT ;
    USE SIGNAL ;
    PORT
      LAYER M4 ;
        RECT  769.916 22.176 770 22.2 ;
    END
  END q[69]
  PIN q[6]
    DIRECTION OUTPUT ;
    USE SIGNAL ;
    PORT
      LAYER M4 ;
        RECT  769.916 16.128 770 16.152 ;
    END
  END q[6]
  PIN q[70]
    DIRECTION OUTPUT ;
    USE SIGNAL ;
    PORT
      LAYER M4 ;
        RECT  769.916 22.272 770 22.296 ;
    END
  END q[70]
  PIN q[71]
    DIRECTION OUTPUT ;
    USE SIGNAL ;
    PORT
      LAYER M4 ;
        RECT  769.916 22.368 770 22.392 ;
    END
  END q[71]
  PIN q[72]
    DIRECTION OUTPUT ;
    USE SIGNAL ;
    PORT
      LAYER M4 ;
        RECT  769.916 22.464 770 22.488 ;
    END
  END q[72]
  PIN q[73]
    DIRECTION OUTPUT ;
    USE SIGNAL ;
    PORT
      LAYER M4 ;
        RECT  769.916 22.56 770 22.584 ;
    END
  END q[73]
  PIN q[74]
    DIRECTION OUTPUT ;
    USE SIGNAL ;
    PORT
      LAYER M4 ;
        RECT  769.916 22.656 770 22.68 ;
    END
  END q[74]
  PIN q[75]
    DIRECTION OUTPUT ;
    USE SIGNAL ;
    PORT
      LAYER M4 ;
        RECT  769.916 22.752 770 22.776 ;
    END
  END q[75]
  PIN q[76]
    DIRECTION OUTPUT ;
    USE SIGNAL ;
    PORT
      LAYER M4 ;
        RECT  769.916 22.848 770 22.872 ;
    END
  END q[76]
  PIN q[77]
    DIRECTION OUTPUT ;
    USE SIGNAL ;
    PORT
      LAYER M4 ;
        RECT  769.916 22.944 770 22.968 ;
    END
  END q[77]
  PIN q[78]
    DIRECTION OUTPUT ;
    USE SIGNAL ;
    PORT
      LAYER M4 ;
        RECT  769.916 23.04 770 23.064 ;
    END
  END q[78]
  PIN q[79]
    DIRECTION OUTPUT ;
    USE SIGNAL ;
    PORT
      LAYER M4 ;
        RECT  769.916 23.136 770 23.16 ;
    END
  END q[79]
  PIN q[7]
    DIRECTION OUTPUT ;
    USE SIGNAL ;
    PORT
      LAYER M4 ;
        RECT  769.916 16.224 770 16.248 ;
    END
  END q[7]
  PIN q[80]
    DIRECTION OUTPUT ;
    USE SIGNAL ;
    PORT
      LAYER M4 ;
        RECT  769.916 23.232 770 23.256 ;
    END
  END q[80]
  PIN q[81]
    DIRECTION OUTPUT ;
    USE SIGNAL ;
    PORT
      LAYER M4 ;
        RECT  769.916 23.328 770 23.352 ;
    END
  END q[81]
  PIN q[82]
    DIRECTION OUTPUT ;
    USE SIGNAL ;
    PORT
      LAYER M4 ;
        RECT  769.916 23.424 770 23.448 ;
    END
  END q[82]
  PIN q[83]
    DIRECTION OUTPUT ;
    USE SIGNAL ;
    PORT
      LAYER M4 ;
        RECT  769.916 23.52 770 23.544 ;
    END
  END q[83]
  PIN q[84]
    DIRECTION OUTPUT ;
    USE SIGNAL ;
    PORT
      LAYER M4 ;
        RECT  769.916 23.616 770 23.64 ;
    END
  END q[84]
  PIN q[85]
    DIRECTION OUTPUT ;
    USE SIGNAL ;
    PORT
      LAYER M4 ;
        RECT  769.916 23.712 770 23.736 ;
    END
  END q[85]
  PIN q[86]
    DIRECTION OUTPUT ;
    USE SIGNAL ;
    PORT
      LAYER M4 ;
        RECT  769.916 23.808 770 23.832 ;
    END
  END q[86]
  PIN q[87]
    DIRECTION OUTPUT ;
    USE SIGNAL ;
    PORT
      LAYER M4 ;
        RECT  769.916 23.904 770 23.928 ;
    END
  END q[87]
  PIN q[88]
    DIRECTION OUTPUT ;
    USE SIGNAL ;
    PORT
      LAYER M4 ;
        RECT  769.916 24 770 24.024 ;
    END
  END q[88]
  PIN q[89]
    DIRECTION OUTPUT ;
    USE SIGNAL ;
    PORT
      LAYER M4 ;
        RECT  769.916 24.096 770 24.12 ;
    END
  END q[89]
  PIN q[8]
    DIRECTION OUTPUT ;
    USE SIGNAL ;
    PORT
      LAYER M4 ;
        RECT  769.916 16.32 770 16.344 ;
    END
  END q[8]
  PIN q[90]
    DIRECTION OUTPUT ;
    USE SIGNAL ;
    PORT
      LAYER M4 ;
        RECT  769.916 24.192 770 24.216 ;
    END
  END q[90]
  PIN q[91]
    DIRECTION OUTPUT ;
    USE SIGNAL ;
    PORT
      LAYER M4 ;
        RECT  769.916 24.288 770 24.312 ;
    END
  END q[91]
  PIN q[92]
    DIRECTION OUTPUT ;
    USE SIGNAL ;
    PORT
      LAYER M4 ;
        RECT  769.916 24.384 770 24.408 ;
    END
  END q[92]
  PIN q[93]
    DIRECTION OUTPUT ;
    USE SIGNAL ;
    PORT
      LAYER M4 ;
        RECT  769.916 24.48 770 24.504 ;
    END
  END q[93]
  PIN q[94]
    DIRECTION OUTPUT ;
    USE SIGNAL ;
    PORT
      LAYER M4 ;
        RECT  769.916 24.576 770 24.6 ;
    END
  END q[94]
  PIN q[95]
    DIRECTION OUTPUT ;
    USE SIGNAL ;
    PORT
      LAYER M4 ;
        RECT  769.916 24.672 770 24.696 ;
    END
  END q[95]
  PIN q[96]
    DIRECTION OUTPUT ;
    USE SIGNAL ;
    PORT
      LAYER M4 ;
        RECT  769.916 24.768 770 24.792 ;
    END
  END q[96]
  PIN q[97]
    DIRECTION OUTPUT ;
    USE SIGNAL ;
    PORT
      LAYER M4 ;
        RECT  769.916 24.864 770 24.888 ;
    END
  END q[97]
  PIN q[98]
    DIRECTION OUTPUT ;
    USE SIGNAL ;
    PORT
      LAYER M4 ;
        RECT  769.916 24.96 770 24.984 ;
    END
  END q[98]
  PIN q[99]
    DIRECTION OUTPUT ;
    USE SIGNAL ;
    PORT
      LAYER M4 ;
        RECT  769.916 25.056 770 25.08 ;
    END
  END q[99]
  PIN q[9]
    DIRECTION OUTPUT ;
    USE SIGNAL ;
    PORT
      LAYER M4 ;
        RECT  769.916 16.416 770 16.44 ;
    END
  END q[9]
  PIN rst_n
    DIRECTION INPUT ;
    USE SIGNAL ;
    PORT
      LAYER M4 ;
        RECT  0 48.48 0.084 48.504 ;
    END
  END rst_n
  PIN VDD
    DIRECTION INOUT ;
    USE POWER ;
    PORT
      LAYER M6 ;
        RECT  1.08 61.233 768.906 61.521 ;
        RECT  1.08 55.833 768.906 56.121 ;
        RECT  1.08 50.433 768.906 50.721 ;
        RECT  1.08 45.033 768.906 45.321 ;
        RECT  1.08 39.633 768.906 39.921 ;
        RECT  1.08 34.233 768.906 34.521 ;
        RECT  1.08 28.833 768.906 29.121 ;
        RECT  1.08 23.433 768.906 23.721 ;
        RECT  1.08 18.033 768.906 18.321 ;
        RECT  1.08 12.633 768.906 12.921 ;
        RECT  1.08 7.233 768.906 7.521 ;
        RECT  1.08 1.833 768.906 2.121 ;
    END
  END VDD
  PIN VSS
    DIRECTION INOUT ;
    USE GROUND ;
    PORT
      LAYER M6 ;
        RECT  1.08 60.849 768.906 61.137 ;
        RECT  1.08 55.449 768.906 55.737 ;
        RECT  1.08 50.049 768.906 50.337 ;
        RECT  1.08 44.649 768.906 44.937 ;
        RECT  1.08 39.249 768.906 39.537 ;
        RECT  1.08 33.849 768.906 34.137 ;
        RECT  1.08 28.449 768.906 28.737 ;
        RECT  1.08 23.049 768.906 23.337 ;
        RECT  1.08 17.649 768.906 17.937 ;
        RECT  1.08 12.249 768.906 12.537 ;
        RECT  1.08 6.849 768.906 7.137 ;
        RECT  1.08 1.449 768.906 1.737 ;
    END
  END VSS
  OBS
    LAYER RVTN ;
     RECT  0 1.057 770 62.933 ;
    LAYER RVTP ;
     RECT  0 1.057 770 62.933 ;
    LAYER M1 ;
     RECT  0 1.057 770 62.933 ;
    LAYER M2 ;
     RECT  0 1.057 770 62.933 ;
    LAYER M3 ;
     RECT  0 1.057 770 62.933 ;
    LAYER M4 ;
     RECT  0 1.057 770 62.933 ;
    LAYER M5 ;
     RECT  0 1.057 770 62.933 ;
    LAYER M6 ;
     RECT  0 1.057 770 62.933 ;
    LAYER M7 ;
     RECT  0 1.057 770 62.933 ;
  END
END ot_v41x_karb_link_cut
END LIBRARY
